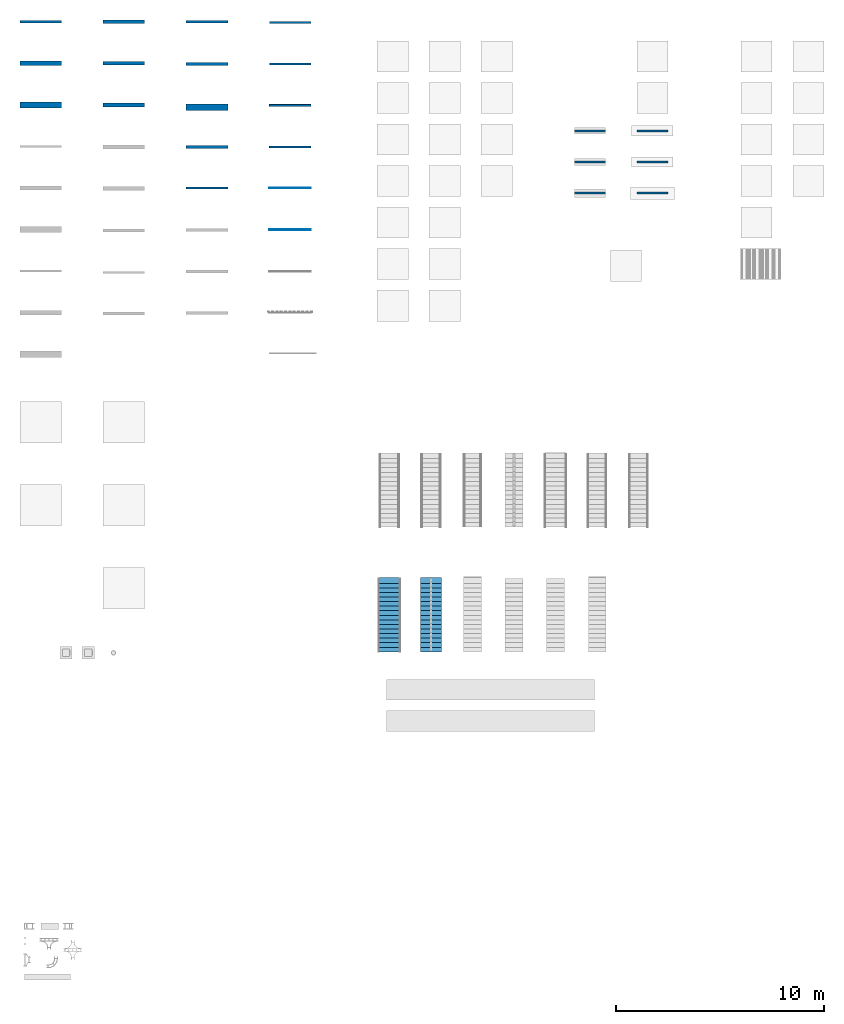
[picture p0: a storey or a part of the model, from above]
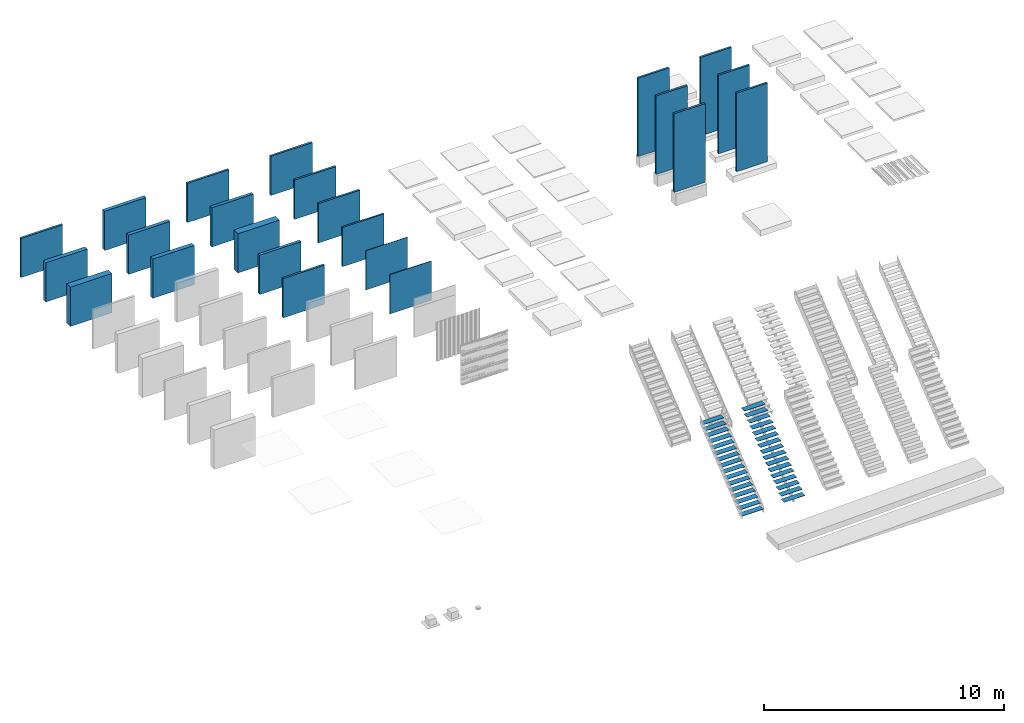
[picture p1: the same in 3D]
Properties of the parts of a building model (IFC2X3), part 1 of 3

# File
Description: ViewDefinition [CoordinationView_V2.0]
File name: 2012C-006
Time: 2013-12-05T17:48:52
Written by: The EXPRESS Data Manager Version 5.01.0100.02.64mod : 6 Jun 2012
Made in: 20130308_1515(x64) - Exporter 3.5.0.0 - Alternate UI 2.5.0.0
Comment: STEP Physical File produced by: The EXPRESS Data Manager Version 5.01.0100.02.64mod : 6 Jun 2012 * Module: EDMstepFileFactory/EDMstandAlone * Creation date: Thu Dec 05 17:48:52 2013 * Host: MDR_LPTP_BTO * Database: C:\Users\Martijn\AppData\Local\Temp\{F84D967D-EF22-411A-948F-E8C0A9D42476}\ifc * Database version: 5507 * Database creation date: Thu Dec 05 17:48:46 2013 * Schema: IFC2X3 * Model: DataRepository.ifc * Model creation date: Thu Dec 05 17:48:46 2013 * Header model: DataRepository.ifc_HeaderModel * Header model creation date: Thu Dec 05 17:48:46 2013 * EDMuser: sdai-user * EDMgroup: sdai-group * License ID and type: 5605 : Permanent license. Expiry date: * EDMstepFileFactory options: 020000

# IfcProject, 2012C-006
LongName: Dutch Revit Standards; Phase: VOORLOPIG

# IfcSite, Surface:79234
RefLatitude: 42, 24, 53, 508911; RefLongitude: -71, -15, -29, -58837; RefElevation: 0 mm
Dimensions - Projected Area: 13.67 m2; Surface Area: 13.67 m2
Identity Data - Name: 90_site
Materials and Finishes - Material: 97_terreinbeplanting_gras
Phasing - Phase Created: Renvooi

# IfcBuilding
Pset_BuildingCommon - NumberOfStoreys: 1
Identity Data - leverancier_bedrijfsnaam: Revit GebruikersGroep; leverancier_email: info@revitgg.nl; leverancier_fax: +31 (0)318 64 85 03; leverancier_plaats: Ede; leverancier_postadres: Postbus 7001; leverancier_postcode: 6710 CB; leverancier_telefoonnummer: +31 (0)318 69 84 57; opdrachtgever_bedrijfsnaam: Revit GebruikersGroep; project_huisadres: Horaplantsoen 20; project_plaats: Ede; project_postcode: 6717 LT; rgd_objectnummer: objectnummer
Other - Project Name: Dutch Revit Standards; Project Number: 2012C-006; Project Status: VOORLOPIG
Text - opdrachtgever_projectmanager: opdrachtgever_projectmanager

# IfcBuildingStorey, 00_begane grond
LongName: 00_begane grond; Elevation: 0 mm
Graphics - Color: 0; Line Pattern: -3000010; Line Weight: 1; Symbol: 00_LAB_niveau: structural_links; Symbol at End 1 Default: yes; Symbol at End 2 Default: no
Constraints - Elevation Base: Project Base Point; Elevation: -1000 mm
Identity Data - Building Story: no; Name: -1_fundering; Structural: yes
Extents - Scope Box: totaal
Dimensions - Computation Height: 0 mm

# IfcCovering: Basic Ceiling:45_CEI_plafond_MEP_host, Basic Ceiling:45_CEI_plafond_MEP_host:55413
In: 00_begane grond
PredefinedType: CEILING
Pset_CoveringCommon - Reference: 45_CEI_plafond_MEP_host
Constraints - Height Offset From Level: 2600 mm; Level: Level: 00_begane grond; Room Bounding: yes
Dimensions - Area: 4 m2; Perimeter: 8000 mm
Fire Protection - brandwerend: no; ontvlambaar: no
Phasing - Phase Created: Renvooi
Analytical Properties - Absorptance: 0.1; Roughness: 1
Identity Data - Description: te gebruiken om MEP elementen op te hosten; Type Mark: 45-99

# IfcCovering: Compound Ceiling:45_CEI_plafond_gipsplaat_610mm_wit, Compound Ceiling:45_CEI_plafond_gipsplaat_610mm_wit:58956
In: 00_begane grond
PredefinedType: CEILING; Material: <Unnamed> 24 mm, 45_gips_plafond_beplating_610mm 12.5 mm
Constraints - Height Offset From Level: 2600 mm; Level: Level: 00_begane grond; Room Bounding: yes
Dimensions - Area: 4 m2; Perimeter: 8000 mm; Volume: 0.146 m3
Fire Protection - brandwerend: no; ontvlambaar: no
Phasing - Phase Created: Renvooi
Analytical Properties - Absorptance: 0.1; Heat Transfer Coefficient (U): 52; Roughness: 1; Thermal mass: 11550; Thermal Resistance (R): 0.0192308
Construction - Thickness: 36.5 mm
Graphics - Coarse Scale Fill Color: 0
Identity Data - Assembly Code: 2H(45.11); Description: gipsplaat plafond op regelwerk; Keynote: d-40-046; Type Comments: platen 610mm breed; Type Mark: 45-01

# IfcCovering: Compound Ceiling:45_CEI_systeemplafond_1200x600_wit, Compound Ceiling:45_CEI_systeemplafond_1200x600_wit:59181
In: 00_begane grond
PredefinedType: CEILING; Material: 45_plafond_systeemplafond_1200x600_wit 15 mm
Pset_CoveringCommon - Reference: 45_CEI_systeemplafond_1200x600_wit; Finish: 45_plafond_systeemplafond_1200x600_wit;; TotalThickness: 4572 mm
Constraints - Height Offset From Level: 2600 mm; Level: Level: 00_begane grond; Room Bounding: yes
Dimensions - Area: 4 m2; Perimeter: 8000 mm; Volume: 0.06 m3
Fire Protection - brandwerend: no; ontvlambaar: no
Phasing - Phase Created: Renvooi
Analytical Properties - Absorptance: 0.1; Heat Transfer Coefficient (U): 3.8; Roughness: 1; Thermal mass: 5829; Thermal Resistance (R): 0.263158
Construction - Thickness: 15 mm
Graphics - Coarse Scale Fill Color: 0
Identity Data - Assembly Code: 2H(45.12); Description: systeemplafond, tegels 1200x600mm; Keynote: d-40-000; Type Comments: wit gekleurd; Type Mark: 45-04

# IfcCovering: Compound Ceiling:45_CEI_systeemplafond_600x600_rood, Compound Ceiling:45_CEI_systeemplafond_600x600_rood:59157
In: 00_begane grond
PredefinedType: CEILING; Material: 45_plafond_systeemplafond_600x600_donkerrood 15 mm
Pset_CoveringCommon - Reference: 45_CEI_systeemplafond_600x600_rood; Finish: 45_plafond_systeemplafond_600x600_donkerrood;; TotalThickness: 4572 mm
Constraints - Height Offset From Level: 2600 mm; Level: Level: 00_begane grond; Room Bounding: yes
Dimensions - Area: 4 m2; Perimeter: 8000 mm; Volume: 0.06 m3
Fire Protection - brandwerend: no; ontvlambaar: no
Phasing - Phase Created: Renvooi
Analytical Properties - Absorptance: 0.1; Heat Transfer Coefficient (U): 3.8; Roughness: 1; Thermal mass: 5829; Thermal Resistance (R): 0.263158
Construction - Thickness: 15 mm
Graphics - Coarse Scale Fill Color: 0
Identity Data - Assembly Code: 2H(45.12); Description: systeemplafond, tegels 600x600mm; Keynote: d-40-000; Type Comments: rood gekleurd; Type Mark: 45-02

# IfcCovering: Compound Ceiling:45_CEI_systeemplafond_600x600_wit, Compound Ceiling:45_CEI_systeemplafond_600x600_wit:59123
In: 00_begane grond
PredefinedType: CEILING; Material: 45_plafond_systeemplafond_600x600_wit 15 mm
Pset_CoveringCommon - Reference: 45_CEI_systeemplafond_600x600_wit; Finish: 45_plafond_systeemplafond_600x600_wit;; TotalThickness: 4572 mm
Constraints - Height Offset From Level: 2600 mm; Level: Level: 00_begane grond; Room Bounding: yes
Dimensions - Area: 4 m2; Perimeter: 8000 mm; Volume: 0.06 m3
Fire Protection - brandwerend: no; ontvlambaar: no
Phasing - Phase Created: Renvooi
Analytical Properties - Absorptance: 0.1; Heat Transfer Coefficient (U): 3.8; Roughness: 1; Thermal mass: 5829; Thermal Resistance (R): 0.263158
Construction - Thickness: 15 mm
Graphics - Coarse Scale Fill Color: 0
Identity Data - Assembly Code: 2H(45.12); Description: systeemplafond, tegels 600x600mm; Keynote: d-40-000; Type Comments: wit gekleurd; Type Mark: 45.03

# IfcCurtainWall: Curtain Wall:21_CW_binnendoos_SAB90_500, Curtain Wall:21_CW_binnendoos_SAB90_500:160824
In: 00_begane grond
Type - Construction - Automatically Embed: no; Curtain Panel: 27_CWP_SAB90_500: SAB90_500; Function: Exterior; Join Condition: Not Defined
Type - Fire Protection - ontvlambaar: no
Type - Horizontal Grid - Adjust for Mullion Size: yes; Layout: Fixed Distance; Spacing: 500 mm
Type - Identity Data - Assembly Code: 2D(21.13); Description: binnendoos SAB90; Type Comments: paneelbreedte 500mm; Type Mark: 41-01
Type - Vertical Grid - Adjust for Mullion Size: no; Spacing: 100 mm
Pset_CurtainWallCommon - Reference: 21_CW_binnendoos_SAB90_500; IsExternal: yes
Constraints - Base Constraint: Level: 00_begane grond; Base is Attached: no; Base Offset: 0 mm; Related to Mass: no; Room Bounding: yes; Top is Attached: no; Top Offset: 0 mm; Unconnected Height: 2000 mm
Dimensions - Area: 4.56 m2; Length: 2280 mm
Fire Protection - brandwerend: no
Horizontal Grid - Angle: 0 deg; Justification: Beginning; Number: 3; Offset: 0 mm
Phasing - Phase Created: Renvooi
Structural - Enable Analytical Model: no; Structural: no; Structural Usage: Non-bearing
Vertical Grid - Angle: 0 deg; Justification: Beginning; Number: 2; Offset: 0 mm

# IfcCurtainWall: Curtain Wall:21_CW_gevelbeplating_SAB35_1035, Curtain Wall:21_CW_gevelbeplating_SAB35_1035:60482
In: 00_begane grond
Type - Construction - Automatically Embed: no; Curtain Panel: 21_CWP_SAB35_1035: SAB35_1035; Function: Exterior; Join Condition: Not Defined
Type - Fire Protection - ontvlambaar: no
Type - Horizontal Grid - Adjust for Mullion Size: no
Type - Identity Data - Assembly Code: 2D(41.12); Description: buitenwandafwerking, bekleding, SAB35; Type Comments: paneelbreedte 1035mm; Type Mark: 41-02
Type - Vertical Grid - Adjust for Mullion Size: no; Layout: Fixed Distance; Spacing: 1035 mm
Pset_CurtainWallCommon - Reference: 21_CW_gevelbeplating_SAB35_1035; IsExternal: yes
Constraints - Base Constraint: Level: 00_begane grond; Base is Attached: no; Base Offset: 0 mm; Related to Mass: no; Room Bounding: yes; Top is Attached: no; Top Offset: 0 mm; Unconnected Height: 2000 mm
Dimensions - Area: 4.14 m2; Length: 2070 mm
Fire Protection - brandwerend: no
Horizontal Grid - Angle: 0 deg; Justification: Beginning; Number: 4; Offset: 0 mm
Phasing - Phase Created: Renvooi
Structural - Enable Analytical Model: no; Structural: no; Structural Usage: Non-bearing
Vertical Grid - Angle: 0 deg; Justification: Beginning; Number: 1; Offset: 0 mm

# IfcFlowFitting: T-stuk, radius_300, 61_CTF_kabelgoot_open_Tsplitsing:T-stuk, radius_300:191225
In: 00_begane grond
Type - Classification: 3B(61.30) (Uniformat)
Type - Dimensions - Radius: 300 mm
Type - Identity Data - Assembly Code: 3B(61.30); Description: kabelgoot, open; Type Comments: T-stuk, radius 300mm; Type Mark: 61-04-01
Constraints - Host: Level : 00_begane grond; Level: Level: 00_begane grond; Offset: 0 mm
Dimensions - Rung Height: 25 mm; Rung Space: 225 mm; Rung Width: 25 mm; Size: 150 mmx100 mmø-150 mmx100 mmø-150 mmx100 mmø; Thickness: 25 mm; Tray Height: 100 mm; Tray Length: 80 mm; Tray Width 1: 150 mm; Tray Width 3: 150 mm
Graphics - Use Annotation Scale: yes
Identity Data - Mark: 5
Other - lengte_1: 273.861 mm; lengte_2: 101.139 mm; lengte_3: 750 mm; radius_label: 300 mm; radius_label_1: 325 mm; zichtbaarheid_1: yes; zichtbaarheid_2: no; zichtbaarheid_3: yes; zichtbaarheid_4: yes
Phasing - Phase Created: Renvooi

# IfcFlowFitting: bocht verticaal binnen, standaard, 61_CTF_kabelgoot_open_bocht_verticaal_binnen:bocht verticaal binnen, standaard:195199
In: 00_begane grond
Type - Classification: 3B(61.30) (Uniformat)
Type - Identity Data - Assembly Code: 3B(61.30); Description: kabelgoot, open; Type Comments: bocht verticaal, binnen; Type Mark: 61-02-01
Constraints - Host: Level : 00_begane grond; Level: Level: 00_begane grond; Offset: 492.42 mm
Dimensions - Angle: 90 deg; Bend Radius: 300 mm; Rung Height: 25.4 mm; Rung Space: 250 mm; Rung Width: 25.4 mm; Size: 300 mmx100 mmø-300 mmx100 mmø; Thickness: 25.4 mm; Tray Height: 100 mm; Tray Length: 80 mm; Tray Width: 300 mm
Graphics - Use Annotation Scale: yes
Identity Data - Mark: 6
Other - Bend or Fitting: Fitting; Bend Radius Label: 350 mm; booglengte: 549.78 mm; hoek_1: 45 deg; hoek_2: 180 deg; hoek_3: 22.5 deg; hoek_4: 67.5 deg; lengte_1: 350 mm; lengte_2: 387.3 mm; sport_lengte: 249.2 mm; sport_lengte_half: 12.7 mm; zichtbaar_1: yes; zichtbaar_2: no
Phasing - Phase Created: Renvooi

# IfcFlowFitting: bocht verticaal buiten, standaard, 61_CTF_kabelgoot_open_bocht_verticaal_buiten:bocht verticaal buiten, standaard:188274
In: 00_begane grond
Type - Classification: 3B(61.30) (Uniformat)
Type - Identity Data - Assembly Code: 3B(61.30); Description: kabelgoot, open; Type Comments: bocht verticaal, buiten; Type Mark: 61-03-01
Constraints - Host: Level : 00_begane grond; Level: Level: 00_begane grond; Offset: 492.42 mm
Dimensions - Bend Radius: 300 mm; hoek: 90 deg; Rung Height: 25.4 mm; Rung Space: 228.6 mm; Rung Width: 25.4 mm; Size: 300 mmx100 mmø-300 mmx100 mmø; Thickness: 25.4 mm; Tray Height: 100 mm; Tray Length: 80 mm; Tray Width: 300 mm
Graphics - Use Annotation Scale: yes
Identity Data - Mark: 4
Other - Bend or Fitting: Fitting; boog_lengte: 549.78 mm; buigstraal_buitenrand: 350 mm; hoek_2: 180 deg; hoek_3: 22.5 deg; hoek_4: 67.5 deg; hoek 1: 45 deg; lengte_1: 312.7 mm; lengte_2: 350 mm; sport_breedte_half: 12.7 mm; sport_lengte: 249.2 mm; zichtbaar 1: yes; zichtbaar 2: no
Phasing - Phase Created: Renvooi

# IfcFlowFitting: bocht, standaard, 61_CTF_kabelgoot_open_bocht_horizontaal:bocht, standaard:207840
In: 00_begane grond
Type - Classification: 3B(61.30) (Uniformat)
Type - Identity Data - Assembly Code: 3B(61.30); Description: kabelgoot, open; Type Comments: bocht horizontaal; Type Mark: 61-07-01
Constraints - Host: Level : 00_begane grond; Level: Level: 00_begane grond; Offset: 0 mm
Dimensions - Angle: 90 deg; Bend Radius: 300 mm; Rung Height: 25 mm; Rung Space: 225 mm; Rung Width: 25 mm; Size: 150 mmx100 mmø-150 mmx100 mmø; Thickness: 25 mm; Tray Height: 100 mm; Tray Length: 80 mm; Tray Width: 150 mm
Graphics - Use Annotation Scale: yes
Identity Data - Mark: 9
Other - Bend or Fitting: Fitting; booglengte: 589.05 mm; buigstraal_midden: 375 mm; hoek_1: 45 deg; hoek_2: 180 deg; hoek_3: 22.5 deg; hoek_4: 67.5 deg; lengte_1: 375 mm; lengte_2: 325 mm; lengte_3: 100 mm; offset: 50 mm; zichtbaar_1: yes; zichtbaar_2: no
Phasing - Phase Created: Renvooi

# IfcFlowFitting: kruising, radius_300, 61_CTF_kabelgoot_open_kruising:kruising, radius_300:217844
In: 00_begane grond
Type - Classification: 3B(61.30) (Uniformat)
Type - Dimensions - Radius: 300 mm
Type - Identity Data - Assembly Code: 3B(61.30); Description: kabelgoot, open; Type Comments: kruising, radius 300mm; Type Mark: 61-08-01
Constraints - Host: Level : 00_begane grond; Level: Level: 00_begane grond; Offset: 0 mm
Dimensions - Rung Height: 25 mm; Rung Space: 225 mm; Rung Width: 25 mm; Size: 150 mmx100 mmø-150 mmx100 mmø-150 mmx100 mmø-150 mmx100 mmø; Thickness: 25 mm; Tray Height: 100 mm; Tray Length: 80 mm; Tray Width 1: 150 mm; Tray Width 3: 150 mm
Graphics - Use Annotation Scale: yes
Identity Data - Mark: 10
Other - lengte_1: 273.861 mm; lengte_2: 101.139 mm; lengte_3: 750 mm; radius_boog: 300 mm; radius_boog_1: 325 mm; zichtbaar_1: yes; zichtbaar_2: no; zichtbaar_3: yes; zichtbaar_4: yes
Phasing - Phase Created: Renvooi

# IfcFlowFitting: verbindingsstuk, standaard, 61_CTF_kabelgoot_open_verbinding:verbindingsstuk, standaard:196779
In: 00_begane grond
Type - Classification: 3B(61.30) (Uniformat)
Type - Identity Data - Assembly Code: 3B(61.30); Description: kabelgoot, open; Type Comments: koppelstuk, 100mm; Type Mark: 61-05-01
Constraints - Host: Level : 00_begane grond; Level: Level: 00_begane grond; Offset: 0 mm
Dimensions - Bend Radius: 300 mm; Rung Height: 25 mm; Rung Space: 225 mm; Rung Width: 25 mm; Size: 300 mmx100 mmø-300 mmx100 mmø; Thickness: 25 mm; Tray Height: 100 mm; Tray Length: 75 mm; Tray Width: 300 mm
Graphics - Use Annotation Scale: yes
Identity Data - Mark: 7
Phasing - Phase Created: Renvooi

# IfcFlowFitting: verloopstuk, standaard, 61_CTF_kabelgoot_open_verloop:verloopstuk, standaard:206094
In: 00_begane grond
Type - Classification: 3B(61.30) (Uniformat)
Type - Identity Data - Assembly Code: 3B(61.30); Description: kabelgoot, open; Type Comments: verloopstuk; Type Mark: 61-06-01
Constraints - Host: Level : 00_begane grond; Level: Level: 00_begane grond; Offset: 0 mm
Dimensions - OffsetHeight: 0.164042; OffsetWidth: 0.984252; Rung Height: 25 mm; Rung Space: 225 mm; Rung Width: 25 mm; Size: 600 mmx100 mmø-300 mmx100 mmø; Thickness: 25 mm; Tray Height 1: 100 mm; Tray Height 2: 100 mm; Tray Length: 300 mm; Tray Width 1: 600 mm; Tray Width 2: 300 mm
Graphics - Use Annotation Scale: yes
Identity Data - Mark: 8
Other - breedte_offset: 3048 mm; hoogte_offset: 3048 mm; lengte_1: 3048 mm; offset_1: 50 mm; offset_2: 50 mm; profiel_offset_horizontaal: 0 mm; profiel_offset_verticaal: 0 mm
Phasing - Phase Created: Renvooi

# IfcFlowSegment: Cable Tray with Fittings:61_CT_kabelgoot_open, Cable Tray with Fittings:61_CT_kabelgoot_open:180304
In: 00_begane grond
Type - Electrical - Bend Radius Multiplier: 1
Type - Fittings - Cross: 61_CTF_kabelgoot_open_kruising: kruising, radius_300; Horizontal Bend: 61_CTF_kabelgoot_open_bocht_horizontaal: bocht, standaard; Tee: 61_CTF_kabelgoot_open_Tsplitsing: T-stuk, radius_300; Transition: 61_CTF_kabelgoot_open_verloop: verloopstuk, standaard; Union: 61_CTF_kabelgoot_open_verbinding: verbindingsstuk, standaard; Vertical Inside Bend: 61_CTF_kabelgoot_open_bocht_verticaal_binnen: bocht verticaal binnen, standaard; Vertical Outside Bend: 61_CTF_kabelgoot_open_bocht_verticaal_buiten: bocht verticaal buiten, standaard
Type - Identity Data - Assembly Code: 3B(61.3); Description: kabelgoot, open; Type Comments: met koppelstukken; Type Mark: 61-01-01
Pset_DistributionFlowElementCommon - Reference: 61_CT_kabelgoot_open
Constraints - End Offset: 492.42 mm; Horizontal Justification: Center; Offset: 492.42 mm; Reference Level: Level: 00_begane grond; Start Offset: 492.42 mm; Vertical Justification: Middle
Dimensions - Height: 100 mm; Length: 860 mm; Rung Space: 250 mm; Size: 300 mmx100 mmø; Width: 300 mm
Electrical - Bottom Elevation: 442.42 mm; Top Elevation: 542.42 mm
Identity Data - Mark: 2
Phasing - Phase Created: Renvooi

# IfcFlowSegment: Cable Tray without Fittings:61_CT_kabelgoot_open, Cable Tray without Fittings:61_CT_kabelgoot_open:206202
In: 00_begane grond
Type - Electrical - Bend Radius Multiplier: 1
Type - Identity Data - Assembly Code: 3B(61.3); Description: kabelgoot, open; Type Comments: zonder koppelstukken; Type Mark: 61-01-02
Pset_DistributionFlowElementCommon - Reference: 61_CT_kabelgoot_open
Constraints - End Offset: 0 mm; Horizontal Justification: Center; Offset: 0 mm; Reference Level: Level: 00_begane grond; Start Offset: 0 mm; Vertical Justification: Middle
Dimensions - Height: 100 mm; Length: 2220 mm; Rung Space: 228.6 mm; Size: 300 mmx100 mmø; Width: 300 mm
Electrical - Bottom Elevation: -50 mm; Top Elevation: 50 mm
Identity Data - Mark: 3
Phasing - Phase Created: Renvooi

# IfcFlowTerminal: aanvoer_plafondrooster_kanaaldiameter_250, 57_AT_plafondrooster_toev_rond_kanaal_FB:aanvoer_plafondrooster_kanaaldiameter_250:221553
In: 00_begane grond
Type - Classification: 3A(57.5) (Uniformat)
Type - Constraints - Default Elevation: 1219.2 mm
Type - Dimensions - breedte_plafondplaat: 600 mm; diameter_aansluiting: 250 mm; kanaal_radius: 125 mm; lengte_plafondplaat: 600 mm; plenum_breedte: 350 mm; plenum_hoogte: 330 mm; plenum_lengte: 350 mm
Type - Identity Data - Assembly Code: 3A(57.5); Description: aanvoerpunt plafondplaat; Manufacturer: RevitGG; Type Comments: kanaaldiameter = 250mm; Type Mark: AT-06-05; URL: www.revitgg.nl
Type - Mechanical - Flow - statisch_drukverlies: 0
Type - Pset_AirTerminalTypeCommon - Shape: ROUND
Pset_ManufacturerTypeInformation - Manufacturer: RevitGG
Constraints - Offset: 0 mm; Work Plane: Level : 00_begane grond
Dimensions - Size: 250 mmø
Identity Data - Mark: 6
Mechanical - System Classification: Supply Air
Mechanical - Flow - debiet_aanvoer: 0 m3/s
Other - Schedule Level: Level: 00_begane grond
Phasing - Phase Created: Renvooi

# IfcFlowTerminal: afvoer_plafondrooster_kanaaldiameter_250, 57_AT_plafondrooster_afv_rond_kanaal_FB:afvoer_plafondrooster_kanaaldiameter_250:124771
In: 00_begane grond
Type - Classification: 3A(57.5) (Uniformat)
Type - Dimensions - breedte_plafondplaat: 600 mm; diameter_aansluiting: 250 mm; kanaal_radius: 125 mm; lengte_plafondplaat: 600 mm; plenum_breedte: 350 mm; plenum_hoogte: 330 mm; plenum_lengte: 350 mm
Type - Identity Data - Assembly Code: 3A(57.5); Description: aanvoerpunt plafondplaat 600x600mm; Manufacturer: RevitGG; Type Comments: kanaaldiameter 250mm; Type Mark: AT-05-05; URL: www.revitgg.nl
Type - Mechanical - Flow - statisch_drukverlies: 0
Type - Pset_AirTerminalTypeCommon - Shape: ROUND
Pset_ManufacturerTypeInformation - Manufacturer: RevitGG
Constraints - Offset: 0 mm; Work Plane: Level : 00_begane grond
Dimensions - Size: 250 mmø
Identity Data - Mark: 5
Mechanical - System Classification: Return Air
Mechanical - Flow - debiet_afzuig: 0 m3/s
Other - Schedule Level: Level: 00_begane grond
Phasing - Phase Created: Renvooi

# IfcFlowTerminal: afvoer_rozet_kanaaldiameter_200, 57_AT_afv_rozet_FB:afvoer_rozet_kanaaldiameter_200:148100
In: 00_begane grond
Type - Classification: 3A(57.30) (Uniformat)
Type - Dimensions - diameter_aansluiting: 200 mm; kanaal_aansluit_hoogte: 50 mm; kanaal_radius: 100 mm; rooster_diameter: 250 mm; rooster_hoogte: 30 mm; rooster_radius: 125 mm
Type - Identity Data - Assembly Code: 3A(57.30); Description: afzuigrozet, generiek; Manufacturer: RevitGG; Type Comments: kanaaldiameter 200mm; Type Mark: AT-07-04; URL: www.revitgg.nl
Type - Mechanical - Flow - statisch_drukverlies: 0
Type - Pset_AirTerminalTypeCommon - Shape: ROUND
Pset_ManufacturerTypeInformation - Manufacturer: RevitGG
Constraints - Offset: 0 mm; Work Plane: Level : 00_begane grond
Dimensions - Size: 200 mmø
Identity Data - Mark: 7
Mechanical - System Classification: Return Air
Mechanical - Flow - debiet_afzuig: 0 m3/s
Other - Schedule Level: Level: 00_begane grond
Phasing - Phase Created: Renvooi

# IfcFooting: Foundation Slab:16_SFO_funderingsplaat_beton_generiek_300, Foundation Slab:16_SFO_funderingsplaat_beton_generiek_300:67787
In: 00_begane grond
Material: layer 300 mm
Constraints - Height Offset From Level: 0 mm; Level: Level: 00_begane grond; Related to Mass: no
Dimensions - Area: 2.25 m2; Elevation at Bottom: -300 mm; Length: 1500 mm; Perimeter: 6000 mm; Thickness: 300 mm; Volume: 0.675 m3; Width: 1500 mm
Phasing - Phase Created: Renvooi
Structural - Enable Analytical Model: yes; Rebar Cover - Bottom Face: Rebar Cover Settings: Rebar Cover 1; Rebar Cover - Other Faces: Rebar Cover Settings: Rebar Cover 1; Rebar Cover - Top Face: Rebar Cover Settings: Rebar Cover 1; Structural: yes
Analytical Properties - Absorptance: 0.1; Heat Transfer Coefficient (U): 3.48667; Roughness: 1; Thermal mass: 453330; Thermal Resistance (R): 0.286807
Construction - Default Thickness: 300 mm
Graphics - Coarse Scale Fill Color: 8421504; Coarse Scale Fill Pattern: Solid fill
Identity Data - Assembly Code: 2A(16.0); Description: Funderingsplaat beton,; Keynote: d-16-000; Type Comments: d = 300mm; Type Mark: 16-01

# IfcFooting: Foundation Slab:16_SFO_funderingsplaat_ihwg_beton_C30/37, Foundation Slab:16_SFO_funderingsplaat_ihwg_beton_C30/37:68150
In: 00_begane grond
Material: 16_beton_ihwg_C30/35 300 mm
Constraints - Height Offset From Level: 0 mm; Level: Level: 00_begane grond; Related to Mass: no
Dimensions - Area: 2.25 m2; Elevation at Bottom: -300 mm; Length: 1500 mm; Perimeter: 6000 mm; Thickness: 300 mm; Volume: 0.675 m3; Width: 1500 mm
Phasing - Phase Created: Renvooi
Structural - Enable Analytical Model: yes; Rebar Cover - Bottom Face: Rebar Cover Settings: Rebar Cover 1; Rebar Cover - Other Faces: Rebar Cover Settings: Rebar Cover 1; Rebar Cover - Top Face: Rebar Cover Settings: Rebar Cover 1; Structural: yes
Analytical Properties - Absorptance: 0.1; Heat Transfer Coefficient (U): 3.48667; Roughness: 1; Thermal mass: 453330; Thermal Resistance (R): 0.286807
Construction - Default Thickness: 300 mm
Graphics - Coarse Scale Fill Color: 8421504; Coarse Scale Fill Pattern: Solid fill
Identity Data - Assembly Code: 2A(16.0); Description: Funderingsplaat beton, in het werk gestort; Keynote: d-16-000; Type Comments: klasse C30/37. d = 300mm; Type Mark: 16-02
Materials and Finishes - Structural Material: 16_beton_ihwg_C30/35

# IfcFooting: Wall Foundation:16_SFO_ihwg beton_C30-35_500x200, Wall Foundation:16_SFO_ihwg beton_C30-35_500x200:317217
In: 00_begane grond
PredefinedType: STRIP_FOOTING; Material: 16_beton_ihwg_C30/35
Structural - Structural Usage: Bearing; Enable Analytical Model: no; Rebar Cover - Bottom Face: Rebar Cover Settings: Rebar Cover 1; Rebar Cover - Other Faces: Rebar Cover Settings: Rebar Cover 1; Rebar Cover - Top Face: Rebar Cover Settings: Rebar Cover 1
Materials and Finishes - Structural Material: 16_beton_ihwg_C30/35
Identity Data - Assembly Code: 2A(16.12); Description: strookfundering ihw gestort beton, C30/35; Keynote: d-16-010; Type Comments: bxh 500x200mm; Type Mark: 16-03
Dimensions - Default End Extension Length: 250 mm; Do Not Break At Inserts: no; Foundation Thickness: 200 mm; Width: 500 mm; Elevation at Bottom: -200 mm; Length: 2000 mm; Volume: 0.2 m3
Constraints - Eccentricity: 0 mm
Phasing - Phase Created: Renvooi

# IfcFooting: Wall Foundation:16_SFO_ihwg beton_C30-35_500x250, Wall Foundation:16_SFO_ihwg beton_C30-35_500x250:317290
In: 00_begane grond
PredefinedType: STRIP_FOOTING; Material: 16_beton_ihwg_C30/35
Structural - Structural Usage: Bearing; Enable Analytical Model: no; Rebar Cover - Bottom Face: Rebar Cover Settings: Rebar Cover 1; Rebar Cover - Other Faces: Rebar Cover Settings: Rebar Cover 1; Rebar Cover - Top Face: Rebar Cover Settings: Rebar Cover 1
Materials and Finishes - Structural Material: 16_beton_ihwg_C30/35
Identity Data - Assembly Code: 2A(16.12); Description: strookfundering ihw gestort beton, C30/35; Keynote: d-16-010; Type Comments: bxh 500x250mm; Type Mark: 16-04
Dimensions - Default End Extension Length: 250 mm; Do Not Break At Inserts: yes; Foundation Thickness: 250 mm; Width: 500 mm; Elevation at Bottom: -250 mm; Length: 2000 mm; Volume: 0.25 m3
Constraints - Eccentricity: 0 mm
Phasing - Phase Created: Renvooi

# IfcFooting: Wall Foundation:16_SFO_ihwg beton_C30-35_600x300, Wall Foundation:16_SFO_ihwg beton_C30-35_600x300:317374
In: 00_begane grond
PredefinedType: STRIP_FOOTING; Material: 16_beton_ihwg_C30/35
Structural - Structural Usage: Bearing; Enable Analytical Model: no; Rebar Cover - Bottom Face: Rebar Cover Settings: Rebar Cover 1; Rebar Cover - Other Faces: Rebar Cover Settings: Rebar Cover 1; Rebar Cover - Top Face: Rebar Cover Settings: Rebar Cover 1
Materials and Finishes - Structural Material: 16_beton_ihwg_C30/35
Identity Data - Assembly Code: 2A(16.12); Description: strookfundering ihw gestort beton, C30/35; Keynote: d-16-010; Type Comments: bxh 600x300mm; Type Mark: 16-05
Dimensions - Default End Extension Length: 300 mm; Do Not Break At Inserts: yes; Foundation Thickness: 300 mm; Width: 600 mm; Elevation at Bottom: -300 mm; Length: 2100 mm; Volume: 0.378 m3
Constraints - Eccentricity: 0 mm
Phasing - Phase Created: Renvooi

# IfcFooting: Wall Foundation:16_SFO_prefab beton_C35-45_300x500, Wall Foundation:16_SFO_prefab beton_C35-45_300x500:317420
In: 00_begane grond
PredefinedType: STRIP_FOOTING; Material: 16_beton_prefab_C35-45
Structural - Structural Usage: Bearing; Enable Analytical Model: no; Rebar Cover - Bottom Face: Rebar Cover Settings: Rebar Cover 1; Rebar Cover - Other Faces: Rebar Cover Settings: Rebar Cover 1; Rebar Cover - Top Face: Rebar Cover Settings: Rebar Cover 1
Materials and Finishes - Structural Material: 16_beton_prefab_C35-45
Identity Data - Assembly Code: 2A(16.12); Description: funderingsbalk prefab beton, C35/45; Keynote: d-16-000; Type Comments: bxh 300xx500mm; Type Mark: 16-06
Dimensions - Default End Extension Length: 0 mm; Do Not Break At Inserts: yes; Foundation Thickness: 500 mm; Width: 300 mm; Elevation at Bottom: -500 mm; Length: 1500 mm; Volume: 0.225 m3
Constraints - Eccentricity: 0 mm
Phasing - Phase Created: Renvooi

# IfcFooting: Wall Foundation:16_SFO_prefab beton_C35-45_350x550, Wall Foundation:16_SFO_prefab beton_C35-45_350x550:317423
In: 00_begane grond
PredefinedType: STRIP_FOOTING; Material: 16_beton_prefab_C35-45
Structural - Structural Usage: Bearing; Enable Analytical Model: no; Rebar Cover - Bottom Face: Rebar Cover Settings: Rebar Cover 1; Rebar Cover - Other Faces: Rebar Cover Settings: Rebar Cover 1; Rebar Cover - Top Face: Rebar Cover Settings: Rebar Cover 1
Materials and Finishes - Structural Material: 16_beton_prefab_C35-45
Identity Data - Assembly Code: 2A(16.12); Description: funderingsbalk prefab beton, C35/45; Keynote: d-16-000; Type Comments: bxh 350xx550mm; Type Mark: 16-07
Dimensions - Default End Extension Length: 0 mm; Do Not Break At Inserts: yes; Foundation Thickness: 550 mm; Width: 350 mm; Elevation at Bottom: -550 mm; Length: 1500 mm; Volume: 0.28875 m3
Constraints - Eccentricity: 0 mm
Phasing - Phase Created: Renvooi

# IfcFooting: Wall Foundation:16_SFO_prefab beton_C35-45_400x600, Wall Foundation:16_SFO_prefab beton_C35-45_400x600:317426
In: 00_begane grond
PredefinedType: STRIP_FOOTING; Material: 16_beton_prefab_C35-45
Structural - Structural Usage: Bearing; Enable Analytical Model: no; Rebar Cover - Bottom Face: Rebar Cover Settings: Rebar Cover 1; Rebar Cover - Other Faces: Rebar Cover Settings: Rebar Cover 1; Rebar Cover - Top Face: Rebar Cover Settings: Rebar Cover 1
Materials and Finishes - Structural Material: 16_beton_prefab_C35-45
Identity Data - Assembly Code: 2A(16.12); Description: funderingsbalk prefab beton, C35/45; Keynote: d-16-000; Type Comments: bxh 400xx600mm; Type Mark: 16-08
Dimensions - Default End Extension Length: 0 mm; Do Not Break At Inserts: yes; Foundation Thickness: 600 mm; Width: 400 mm; Elevation at Bottom: -600 mm; Length: 1500 mm; Volume: 0.36 m3
Constraints - Eccentricity: 0 mm
Phasing - Phase Created: Renvooi

# IfcMember: Carriage:24_STC_middenboom_hout_vuren_100x50 (2)
In: 00_begane grond
Type - PredefinedType: STRINGER
Pset_MemberCommon - LoadBearing: yes; IsExternal: no; Span: 100 mm; Slope: 0 deg
Constraints - Lower End Cut: Vertical Cut; Trim Support at Upper: Do not trim; Upper End Cut: Vertical Cut
Phasing - Phase Created: Renvooi
Dimensions - Structural Depth On Landing: 50 mm; Structural Depth On Run: 50 mm; Total Depth: 350 mm; Width: 100 mm
Fire Protection - ontvlambaar: no
Identity Data - Assembly Code: 2G(24.0); Description: middenboom, vuren, 15x100mm; Keynote: d-24-000; Type Mark: CA_05
Name (Assembled Stair:Stair:...) | Reference
69261 Stringer 1 | 24_ST_houten trap_open_middenboom_b=850_op=185_aan=220
69309 Stringer 1 | 24_ST_stalen trap_open_middenboom_b=1000_op=185_aan=220

# IfcMember: Carriage:24_STC_middenboom_hout_vuren_45x100 (2)
In: 00_begane grond
Type - PredefinedType: STRINGER
Pset_MemberCommon - Reference: 24_ST_houten trap_open_gezadeld_b=850_op=185_aan=220; LoadBearing: yes; IsExternal: no; Span: 45 mm; Slope: 0 deg
Constraints - Lower End Cut: Vertical Cut; Trim Support at Upper: Do not trim; Upper End Cut: Vertical Cut
Phasing - Phase Created: Renvooi
Dimensions - Structural Depth On Landing: 100 mm; Structural Depth On Run: 100 mm; Total Depth: 350 mm; Width: 45 mm
Fire Protection - ontvlambaar: no
Identity Data - Assembly Code: 2G(24.0); Description: middenboom, vuren, 45x100mm; Keynote: d-24-000; Type Mark: CA_03
Name (Assembled Stair:Stair:...)
69257 Stringer 1
69257 Stringer 2

# IfcMember: Stringer:24_STS_trapboom_hout_vuren_15x50 (8)
In: 00_begane grond
Type - PredefinedType: STRINGER
Pset_MemberCommon - LoadBearing: yes; IsExternal: no; Span: 15 mm; Slope: 0 deg
Constraints - Lower End Cut: Vertical Cut; Trim Support at Upper: Do not trim; Upper End Cut: Vertical Cut
Phasing - Phase Created: Renvooi
Dimensions - Flip Section Profile: no; Structural Depth On Landing: 50 mm; Structural Depth On Run: 50 mm; Total Depth: 350 mm; Width: 15 mm
Fire Protection - ontvlambaar: no
Identity Data - Assembly Code: 2G(24.10); Description: trapboom, vuren, 15x50mm; Keynote: d-24-000
Name (Assembled Stair:Stair:...) | Reference
69280 Stringer 1 | 24_ST_stalen trap_gesloten_b=1000_op=185_aan=220
69280 Stringer 2 | 24_ST_stalen trap_gesloten_b=1000_op=185_aan=220
69283 Stringer 1 | 24_ST_stalen trap_open_b=850_op=185_aan=150
69283 Stringer 2 | 24_ST_stalen trap_open_b=850_op=185_aan=150
69288 Stringer 1 | 24_ST_stalen trap_open_b=850_op=185_aan=220
69288 Stringer 2 | 24_ST_stalen trap_open_b=850_op=185_aan=220
69305 Stringer 1 | 24_ST_stalen trap_open_b=1000_op=185_aan=350
69305 Stringer 2 | 24_ST_stalen trap_open_b=1000_op=185_aan=350

# IfcMember: Stringer:24_STS_trapboom_hout_vuren_45x50 (4)
In: 00_begane grond
Type - PredefinedType: STRINGER
Pset_MemberCommon - LoadBearing: yes; IsExternal: no; Span: 45 mm; Slope: 0 deg
Constraints - Lower End Cut: Vertical Cut; Trim Support at Upper: Do not trim; Upper End Cut: Vertical Cut
Phasing - Phase Created: Renvooi
Dimensions - Flip Section Profile: no; Structural Depth On Landing: 50 mm; Structural Depth On Run: 50 mm; Total Depth: 350 mm; Width: 45 mm
Fire Protection - ontvlambaar: no
Identity Data - Assembly Code: 2G(24.10); Description: trapboom, vuren, 45x50mm; Keynote: d-24-000
Name (Assembled Stair:Stair:...) | Reference
68679 Stringer 1 | 24_ST_houten trap_gesloten_b=850_op=185_aan=220
68679 Stringer 2 | 24_ST_houten trap_gesloten_b=850_op=185_aan=220
68953 Stringer 1 | 24_ST_houten trap_open_b=850_op=185_aan=220
68953 Stringer 2 | 24_ST_houten trap_open_b=850_op=185_aan=220

# IfcPlate: SAB35_1035 (2)
In: 00_begane grond
Type - ElementType: SAB35_1035
Type - Analytical Properties - Analytic Construction: <None>
Type - Dimensions - profiel_breedte: 1035 mm; profiel_diepte: 37 mm
Type - Identity Data - Assembly Code: 2D(41.12); Description: gevelbeplating, damwandprofiel, SAB35; OmniClass Number: 23.25.20.14.11.11.17; OmniClass Title: Infill Panels; Type Comments: paneelbreedte 1035mm; Type Mark: 41-02-01
Analysis Results - oppervlakte: 13.44 m2
Constraints - CALC_profiel_offset: 500 mm
Dimensions - Area: 2.07 m2; breedte: 3200 mm; dagmaat: 1035 mm; dagmaat_hoogte: 2000 mm; dikte: 0 mm; Height: 2000 mm; hoogte: 4200 mm; profiel_offset: 0 mm; Width: 1035 mm
Phasing - Phase Created: Renvooi
Pset_PlateCommon - IsExternal: yes; LoadBearing: yes; ThermalTransmittance: 0 kg/K/s3
Name (21_CWP_SAB35_1035:SAB35_1035:...)
60502
157321

# IfcPlate: SAB58KD_945 (2)
In: 00_begane grond
Type - ElementType: SAB58KD_945
Type - Analytical Properties - Analytic Construction: <None>
Type - Dimensions - profiel_breedte: 945 mm; profiel_diepte: 58 mm
Type - Identity Data - Assembly Code: 2C(47.10); Description: kouddak beplating, damwandprofiel, SAB58KD; OmniClass Number: 23.25.20.14.11.11.17; OmniClass Title: Infill Panels; Type Comments: paneelbreedte 945mm; Type Mark: 47-05-01
Analysis Results - oppervlakte: 13.44 m2
Constraints - CALC_profiel_offset: 560 mm
Dimensions - breedte: 3200 mm; dagmaat_hoogte: 1500 mm; dikte: 0 mm; Height: 1500 mm; hoogte: 4200 mm; profiel_offset: 60 mm
Phasing - Phase Created: Renvooi
Pset_PlateCommon - IsExternal: yes; LoadBearing: yes; ThermalTransmittance: 0 kg/K/s3
Name (27_CWP_SAB58KD_945:SAB58KD_945:...) | Area (m2) | dagmaat (mm) = Width (mm)
165322 | 1.4175 | 945
165325 | 0.8325 | 555

# IfcPlate: SAB90_500 (4)
In: 00_begane grond
Type - ElementType: SAB90_500
Type - Analytical Properties - Analytic Construction: <None>
Type - Dimensions - profiel_breedte: 500 mm; profiel_diepte: 92 mm
Type - Fire Protection - ontvlambaar: no
Type - Identity Data - Assembly Code: 2D(21.13); Description: stalen binnendoos, SAB90; OmniClass Number: 23.25.20.14.11.11.17; OmniClass Title: Infill Panels; Type Comments: plaatbreedte 500mm; Type Mark: 41-01-01; zelfsluitend: no
Analysis Results - oppervlakte: 13.44 m2
Constraints - CALC_profiel_offset: 500 mm
Dimensions - Area: 1.14 m2; dagmaat: 2280 mm; dagmaat_hoogte: 500 mm; dikte: 0 mm; Height: 500 mm; profiel_offset: 0 mm; Width: 2280 mm
Phasing - Phase Created: Renvooi
Pset_PlateCommon - IsExternal: yes; LoadBearing: yes; ThermalTransmittance: 0 kg/K/s3
Name (27_CWP_SAB90_500:SAB90_500:...)
160826
168635
168639
168643

# IfcRamp: Ramp:24_RA_hellingbaan_beton_prefab_300:1413, Ramp:24_RA_hellingbaan_beton_prefab_300:77835
In: 00_begane grond
Pset_RampCommon - Reference: 24_RA_hellingbaan_beton_prefab_300; IsExternal: no; HandicapAccessible: no; FireExit: no; HasNonSkidSurface: no; RequiredSlope: 30
Constraints - Base Level: Level: 00_begane grond; Base Offset: 0 mm; Top Level: Level: 01_eerste verdieping; Top Offset: 0 mm
Dimensions - Width: 1000 mm; Maximum Incline Length: 10000 mm
Fire Protection - brandwerend: no; ontvlambaar: no
Graphics - Down label: yes; Down text: DN; Show Up arrow in all views: no; Up label: yes; Up text: UP; Text Font: Arial; Text Size: 0.0082021
Identity Data - antislip: no; toegankelijk: no; vluchtweg: no; Assembly Code: 2G(24.20); Description: hellingbaan, b=1000mm; Keynote: d-24-000; Type Comments: prefab beton, 300mm; Type Mark: 24-14
Phasing - Phase Created: Renvooi
Construction - Function: Interior; Thickness: 300 mm
Materials and Finishes - Ramp Material: 24_beton_prefab_generiek
Other - Ramp Max Slope (1/x): 30; Shape: Thick

# IfcRamp: Ramp:24_RA_hellingbaan_beton_prefab_solid:79073, Ramp:24_RA_hellingbaan_beton_prefab_solid:79050
In: 00_begane grond
Pset_RampCommon - Reference: 24_RA_hellingbaan_beton_prefab_solid; IsExternal: no; HandicapAccessible: no; FireExit: no; HasNonSkidSurface: no; RequiredSlope: 30
Constraints - Base Level: Level: 00_begane grond; Base Offset: 0 mm; Top Level: Level: 01_eerste verdieping; Top Offset: 0 mm
Dimensions - Width: 1000 mm; Maximum Incline Length: 10000 mm
Fire Protection - brandwerend: no; ontvlambaar: no
Graphics - Down label: yes; Down text: DN; Show Up arrow in all views: no; Up label: yes; Up text: UP; Text Font: Arial; Text Size: 0.0082021
Identity Data - antislip: no; toegankelijk: no; vluchtweg: no; Assembly Code: 2G(24.20); Description: hellingbaan, b=1000mm; Keynote: d-24-000; Type Comments: prefab beton, 300mm; Type Mark: 24-15
Phasing - Phase Created: Renvooi
Other - Ramp Max Slope (1/x): 30; Shape: Solid
Materials and Finishes - Ramp Material: 24_beton_prefab_generiek
Construction - Function: Exterior; Thickness: 300 mm

# IfcRampFlight: Ramp:24_RA_hellingbaan_beton_prefab_300:1413, Ramp:24_RA_hellingbaan_beton_prefab_300:77835:1
In: 00_begane grond
Material: 24_beton_prefab_generiek
Pset_RampFlightCommon - Reference: 24_RA_hellingbaan_beton_prefab_300

# IfcRampFlight: Ramp:24_RA_hellingbaan_beton_prefab_solid:79073, Ramp:24_RA_hellingbaan_beton_prefab_solid:79050:1
In: 00_begane grond
Material: 24_beton_prefab_generiek
Pset_RampFlightCommon - Reference: 24_RA_hellingbaan_beton_prefab_solid

# IfcRoof: Basic Roof:27_RO_dakplaat_enkelschalig_PIR_135_33-90-12, Basic Roof:27_RO_dakplaat_enkelschalig_PIR_135_33-90-12:69928
In: 00_begane grond
Pset_RoofCommon - Reference: 27_RO_dakplaat_enkelschalig_PIR_135_33-90-12; IsExternal: yes; TotalArea: 2.25 m2; ProjectedArea: 2.25 m2
Constraints - Base Level: Level: 00_begane grond; Base Offset From Level: 0 mm; Cutoff Offset: 0 mm; Related to Mass: no; Room Bounding: yes
Construction - Fascia Depth: 0 mm; Maximum Ridge Height: 135 mm; Rafter Cut: Plumb Cut; Default Thickness: 135 mm
Dimensions - Area: 2.25 m2; Thickness: 135 mm; Volume: 0.30375 m3
Phasing - Phase Created: Renvooi
Analytical Properties - Absorptance: 0.1; Heat Transfer Coefficient (U): 0.321998; Roughness: 1; Thermal mass: 18473.2; Thermal Resistance (R): 3.10561
Graphics - Coarse Scale Fill Color: 8421504; Coarse Scale Fill Pattern: Solid fill
Identity Data - Assembly Code: 2B(27.22); Description: enkelschalige zelfdragende dakplaat, ribhoogte 123mm; Type Comments: 90mm PIR isolatie, onderplaat 12mm; Type Mark: 27-04

# IfcRoof: Basic Roof:27_RO_dakplaat_sandwich_PIR_106_20-3-80-3, Basic Roof:27_RO_dakplaat_sandwich_PIR_106_20-3-80-3:77055
In: 00_begane grond
Pset_RoofCommon - Reference: 27_RO_dakplaat_sandwich_PIR_106_20-3-80-3; IsExternal: yes; TotalArea: 2.25 m2; ProjectedArea: 2.25 m2
Constraints - Base Level: Level: 00_begane grond; Base Offset From Level: 0 mm; Cutoff Offset: 0 mm; Related to Mass: no; Room Bounding: yes
Construction - Fascia Depth: 0 mm; Maximum Ridge Height: 106 mm; Rafter Cut: Plumb Cut; Default Thickness: 106 mm
Dimensions - Area: 2.25 m2; Thickness: 106 mm; Volume: 0.2385 m3
Phasing - Phase Created: Renvooi
Analytical Properties - Absorptance: 0.1; Heat Transfer Coefficient (U): 0.367638; Roughness: 1; Thermal mass: 11556.1; Thermal Resistance (R): 2.72007
Graphics - Coarse Scale Fill Color: 8421504; Coarse Scale Fill Pattern: Solid fill
Identity Data - Assembly Code: 2B(27.22); Description: sandwich dakplaat, ribhoogte 80mm, tengel 20mm; Type Comments: 80mm PIR isolatie, onder- en bovenplaat 3mm; Type Mark: 27-05

# IfcRoof: Basic Roof:27_RO_generiek_200, Basic Roof:27_RO_generiek_200:69710
In: 00_begane grond
Pset_RoofCommon - Reference: 27_RO_generiek_200; IsExternal: yes; TotalArea: 2.25 m2; ProjectedArea: 2.25 m2
Constraints - Base Level: Level: 00_begane grond; Base Offset From Level: 0 mm; Cutoff Offset: 0 mm; Related to Mass: no; Room Bounding: yes
Construction - Fascia Depth: 0 mm; Maximum Ridge Height: 200 mm; Rafter Cut: Plumb Cut; Default Thickness: 200 mm
Dimensions - Area: 2.25 m2; Thickness: 200 mm; Volume: 0.45 m3
Phasing - Phase Created: Renvooi
Analytical Properties - Absorptance: 0.1; Roughness: 1
Graphics - Coarse Scale Fill Color: 8421504; Coarse Scale Fill Pattern: Solid fill
Identity Data - Assembly Code: 2C(27.0); Description: dak, generiek; Type Comments: d=200mm; Type Mark: 27-01

# IfcRoof: Basic Roof:27_RO_generiek_300, Basic Roof:27_RO_generiek_300:69826
In: 00_begane grond
Pset_RoofCommon - Reference: 27_RO_generiek_300; IsExternal: yes; TotalArea: 2.25 m2; ProjectedArea: 2.25 m2
Constraints - Base Level: Level: 00_begane grond; Base Offset From Level: 0 mm; Cutoff Offset: 0 mm; Related to Mass: no; Room Bounding: yes
Construction - Fascia Depth: 0 mm; Maximum Ridge Height: 300 mm; Rafter Cut: Plumb Cut; Default Thickness: 300 mm
Dimensions - Area: 2.25 m2; Thickness: 300 mm; Volume: 0.675 m3
Phasing - Phase Created: Renvooi
Analytical Properties - Absorptance: 0.1; Roughness: 1
Graphics - Coarse Scale Fill Color: 8421504; Coarse Scale Fill Pattern: Solid fill
Identity Data - Assembly Code: 2C(27.0); Description: dak, generiek; Type Comments: d=300mm; Type Mark: 27-02

# IfcRoof: Basic Roof:27_RO_hout_underlayment_189_171-18, Basic Roof:27_RO_hout_underlayment_189_171-18:69921
In: 00_begane grond
Pset_RoofCommon - Reference: 27_RO_hout_underlayment_189_171-18; IsExternal: yes; TotalArea: 2.25 m2; ProjectedArea: 2.25 m2
Constraints - Base Level: Level: 00_begane grond; Base Offset From Level: 0 mm; Cutoff Offset: 0 mm; Related to Mass: no; Room Bounding: yes
Construction - Fascia Depth: 0 mm; Maximum Ridge Height: 189 mm; Rafter Cut: Plumb Cut; Default Thickness: 189 mm
Dimensions - Area: 2.25 m2; Thickness: 189 mm; Volume: 0.42525 m3
Phasing - Phase Created: Renvooi
Analytical Properties - Absorptance: 0.1; Heat Transfer Coefficient (U): 5.02813; Roughness: 1; Thermal mass: 14315; Thermal Resistance (R): 0.198881
Graphics - Coarse Scale Fill Color: 8421504; Coarse Scale Fill Pattern: Solid fill
Identity Data - Assembly Code: 2B(27.20); Description: houten gordingen; Type Comments: underlayment beplating 18mm; Type Mark: 27-03

# IfcRoof: Basic Roof:47_RO_dakpan_grijs_300x300, Basic Roof:47_RO_dakpan_grijs_300x300:69939
In: 00_begane grond
Pset_RoofCommon - Reference: 47_RO_dakpan_grijs_300x300; IsExternal: yes; TotalArea: 2.25 m2; ProjectedArea: 2.25 m2
Constraints - Base Level: Level: 00_begane grond; Base Offset From Level: 0 mm; Cutoff Offset: 0 mm; Related to Mass: no; Room Bounding: yes
Construction - Fascia Depth: 0 mm; Maximum Ridge Height: 92 mm; Rafter Cut: Plumb Cut; Default Thickness: 92 mm
Dimensions - Area: 2.25 m2; Thickness: 92 mm; Volume: 0.207 m3
Phasing - Phase Created: Renvooi
Analytical Properties - Absorptance: 0.1; Heat Transfer Coefficient (U): 14.152; Roughness: 1; Thermal mass: 105803; Thermal Resistance (R): 0.0706616
Graphics - Coarse Scale Fill Color: 8421504; Coarse Scale Fill Pattern: Solid fill
Identity Data - Assembly Code: 2C(47.22); Description: dakpannen grijs op panlat; Type Mark: 47-03

# IfcRoof: Basic Roof:47_RO_dakpan_rood_300x300, Basic Roof:47_RO_dakpan_rood_300x300:69946
In: 00_begane grond
Pset_RoofCommon - Reference: 47_RO_dakpan_rood_300x300; IsExternal: yes; TotalArea: 2.25 m2; ProjectedArea: 2.25 m2
Constraints - Base Level: Level: 00_begane grond; Base Offset From Level: 0 mm; Cutoff Offset: 0 mm; Related to Mass: no; Room Bounding: yes
Construction - Fascia Depth: 0 mm; Maximum Ridge Height: 92 mm; Rafter Cut: Plumb Cut; Default Thickness: 92 mm
Dimensions - Area: 2.25 m2; Thickness: 92 mm; Volume: 0.207 m3
Phasing - Phase Created: Renvooi
Analytical Properties - Absorptance: 0.1; Heat Transfer Coefficient (U): 14.152; Roughness: 1; Thermal mass: 105803; Thermal Resistance (R): 0.0706616
Graphics - Coarse Scale Fill Color: 8421504; Coarse Scale Fill Pattern: Solid fill
Identity Data - Assembly Code: 2C(47.22); Description: dakpannen rood op panlat; Type Mark: 47-04

# IfcRoof: Basic Roof:47_RO_isolatie_EPS_bitumen_102_100-2, Basic Roof:47_RO_isolatie_EPS_bitumen_102_100-2:69892
In: 00_begane grond
Pset_RoofCommon - Reference: 47_RO_isolatie_EPS_bitumen_102_100-2; IsExternal: yes; TotalArea: 2.25 m2; ProjectedArea: 2.25 m2
Constraints - Base Level: Level: 00_begane grond; Base Offset From Level: 0 mm; Cutoff Offset: 0 mm; Related to Mass: no; Room Bounding: yes
Construction - Fascia Depth: 0 mm; Maximum Ridge Height: 102 mm; Rafter Cut: Plumb Cut; Default Thickness: 102 mm
Dimensions - Area: 2.25 m2; Thickness: 102 mm; Volume: 0.2295 m3
Phasing - Phase Created: Renvooi
Analytical Properties - Absorptance: 0.1; Heat Transfer Coefficient (U): 0.349787; Roughness: 1; Thermal mass: 7295.4; Thermal Resistance (R): 2.85888
Graphics - Coarse Scale Fill Color: 8421504; Coarse Scale Fill Pattern: Solid fill
Identity Data - Assembly Code: 2C(47.25); Description: EPS isolatie 100mm, beloopbaar; Type Comments: 2-laags bitumen; Type Mark: 47-02

# IfcRoof: Basic Roof:47_RO_isolatie_PIR_bitumen_82_80-2, Basic Roof:47_RO_isolatie_PIR_bitumen_82_80-2:69885
In: 00_begane grond
Pset_RoofCommon - Reference: 47_RO_isolatie_PIR_bitumen_82_80-2; IsExternal: yes; TotalArea: 2.25 m2; ProjectedArea: 2.25 m2
Constraints - Base Level: Level: 00_begane grond; Base Offset From Level: 0 mm; Cutoff Offset: 0 mm; Related to Mass: no; Room Bounding: yes
Construction - Fascia Depth: 0 mm; Maximum Ridge Height: 102 mm; Rafter Cut: Plumb Cut; Default Thickness: 102 mm
Dimensions - Area: 2.25 m2; Thickness: 102 mm; Volume: 0.2295 m3
Phasing - Phase Created: Renvooi
Analytical Properties - Absorptance: 0.1; Heat Transfer Coefficient (U): 0.299844; Roughness: 1; Thermal mass: 10529.4; Thermal Resistance (R): 3.33507
Graphics - Coarse Scale Fill Color: 8421504; Coarse Scale Fill Pattern: Solid fill
Identity Data - Assembly Code: 2C(47.21); Description: PIR isolatie 80mm; Type Comments: 2-laags bitumen; Type Mark: 47-01

# IfcRoof: Sloped Glazing:27_CW_SAB58KD_945mm, Sloped Glazing:27_CW_SAB58KD_945mm:165312
In: 00_begane grond
Type - Construction - Curtain Panel: 27_CWP_SAB58KD_945: SAB58KD_945; Join Condition: Not Defined
Type - Grid 1 - Adjust for Mullion Size: no; Layout: Fixed Distance; Spacing: 945 mm
Type - Grid 2 - Adjust for Mullion Size: no
Type - Identity Data - Assembly Code: 2C(47.20); Description: dakplaat SAB 58KD; Type Comments: plaatbreedte 945mm; Type Mark: 47-05
Pset_RoofCommon - Reference: 27_CW_SAB58KD_945mm; IsExternal: yes; ProjectedArea: 2.25 m2
Constraints - Base Level: Level: 00_begane grond; Base Offset From Level: 0 mm; Cutoff Offset: 0 mm; Related to Mass: no; Room Bounding: yes
Construction - Fascia Depth: 0 mm; Maximum Ridge Height: 100 mm; Rafter Cut: Plumb Cut
Dimensions - Thickness: 100 mm
Grid 1 - Angle: 0 deg; Justification: Beginning; Number: 4; Offset: 0 mm; sets with these values: 2
Phasing - Phase Created: Renvooi

# IfcSlab: Basic Roof:27_RO_dakplaat_enkelschalig_PIR_135_33-90-12, Basic Roof:27_RO_dakplaat_enkelschalig_PIR_135_33-90-12:69928
In: 00_begane grond
PredefinedType: ROOF; Material: 00_lucht_spouw_dak_geventileerd 33 mm, 20_isolatie_PIR 90 mm, 20_beplating_MDF 12 mm
Pset_SlabCommon - Reference: 27_RO_dakplaat_enkelschalig_PIR_135_33-90-12; IsExternal: yes; LoadBearing: yes; ThermalTransmittance: 0.321998 kg/K/s3; PitchAngle: 0 deg

# IfcSlab: Basic Roof:27_RO_dakplaat_sandwich_PIR_106_20-3-80-3, Basic Roof:27_RO_dakplaat_sandwich_PIR_106_20-3-80-3:77055
In: 00_begane grond
PredefinedType: ROOF; Material: 27_tengels_geventileerd 20 mm, 20_beplating_MDF 3 mm, 20_isolatie_PIR 80 mm, 20_beplating_MDF 3 mm
Pset_SlabCommon - Reference: 27_RO_dakplaat_sandwich_PIR_106_20-3-80-3; IsExternal: yes; LoadBearing: yes; ThermalTransmittance: 0.367638 kg/K/s3; PitchAngle: 0 deg

# IfcSlab: Basic Roof:27_RO_generiek_200, Basic Roof:27_RO_generiek_200:69710
In: 00_begane grond
PredefinedType: ROOF; Material: Default 200 mm
Pset_SlabCommon - Reference: 27_RO_generiek_200; IsExternal: yes; LoadBearing: yes; PitchAngle: 0 deg

# IfcSlab: Basic Roof:27_RO_generiek_300, Basic Roof:27_RO_generiek_300:69826
In: 00_begane grond
PredefinedType: ROOF; Material: Default 300 mm
Pset_SlabCommon - Reference: 27_RO_generiek_300; IsExternal: yes; LoadBearing: yes; PitchAngle: 0 deg

# IfcSlab: Basic Roof:27_RO_hout_underlayment_189_171-18, Basic Roof:27_RO_hout_underlayment_189_171-18:69921
In: 00_begane grond
PredefinedType: ROOF; Material: 27_beplating_underlayment 18 mm, 27_houten_balklaag_geventileerd 171 mm
Pset_SlabCommon - Reference: 27_RO_hout_underlayment_189_171-18; IsExternal: yes; LoadBearing: yes; ThermalTransmittance: 5.02813 kg/K/s3; PitchAngle: 0 deg

# IfcSlab: Basic Roof:47_RO_dakpan_grijs_300x300, Basic Roof:47_RO_dakpan_grijs_300x300:69939
In: 00_begane grond
PredefinedType: ROOF; Material: 47_dakpan_grijs 70 mm, 47_panlat_geventileerd 22 mm
Pset_SlabCommon - Reference: 47_RO_dakpan_grijs_300x300; IsExternal: yes; LoadBearing: yes; ThermalTransmittance: 14.152 kg/K/s3; PitchAngle: 0 deg

# IfcSlab: Basic Roof:47_RO_dakpan_rood_300x300, Basic Roof:47_RO_dakpan_rood_300x300:69946
In: 00_begane grond
PredefinedType: ROOF; Material: 47_dakpan_rood 70 mm, 47_panlat_geventileerd 22 mm
Pset_SlabCommon - Reference: 47_RO_dakpan_rood_300x300; IsExternal: yes; LoadBearing: yes; ThermalTransmittance: 14.152 kg/K/s3; PitchAngle: 0 deg

# IfcSlab: Basic Roof:47_RO_isolatie_EPS_bitumen_102_100-2, Basic Roof:47_RO_isolatie_EPS_bitumen_102_100-2:69892
In: 00_begane grond
PredefinedType: ROOF; Material: 47_bitumen 2 mm, 20_isolatie_EPS 100 mm
Pset_SlabCommon - Reference: 47_RO_isolatie_EPS_bitumen_102_100-2; IsExternal: yes; LoadBearing: yes; ThermalTransmittance: 0.349787 kg/K/s3; PitchAngle: 0 deg

# IfcSlab: Basic Roof:47_RO_isolatie_PIR_bitumen_82_80-2, Basic Roof:47_RO_isolatie_PIR_bitumen_82_80-2:69885
In: 00_begane grond
PredefinedType: ROOF; Material: 47_bitumen 2 mm, 20_isolatie_PIR 100 mm
Pset_SlabCommon - Reference: 47_RO_isolatie_PIR_bitumen_82_80-2; IsExternal: yes; LoadBearing: yes; ThermalTransmittance: 0.299844 kg/K/s3; PitchAngle: 0 deg

# IfcSlab: Floor:11_FL_werkvloer_stampbeton_50, Floor:11_FL_werkvloer_stampbeton_50:61065
In: 00_begane grond
PredefinedType: FLOOR; Material: 11_werkvloer_stampbeton 50 mm
Pset_SlabCommon - Reference: 11_FL_werkvloer_stampbeton_50; IsExternal: yes; LoadBearing: yes; Combustible: no; Compartmentation: no; ThermalTransmittance: 20.92 kg/K/s3; PitchAngle: 0 deg
Constraints - Height Offset From Level: 0 mm; Level: Level: 00_begane grond; Related to Mass: no; Room Bounding: yes
Dimensions - Area: 2.25 m2; Perimeter: 6000 mm; Thickness: 50 mm; Volume: 0.1125 m3
Fire Protection - brandwerend: no; ontvlambaar: no
Phasing - Phase Created: Renvooi
Structural - Enable Analytical Model: yes; Rebar Cover - Bottom Face: Rebar Cover Settings: Rebar Cover 1; Rebar Cover - Other Faces: Rebar Cover Settings: Rebar Cover 1; Rebar Cover - Top Face: Rebar Cover Settings: Rebar Cover 1; Structural: yes
Analytical Properties - Absorptance: 0.1; Heat Transfer Coefficient (U): 20.92; Roughness: 1; Thermal mass: 75555; Thermal Resistance (R): 0.0478011
Construction - Default Thickness: 50 mm; Function: Exterior
Graphics - Coarse Scale Fill Color: 8421504; Coarse Scale Fill Pattern: Solid fill
Identity Data - Assembly Code: 2A(13.11); Description: werkvloer, stampbeton; Keynote: d-16-000; Type Comments: d=50mm; Type Mark: 11-01
Materials and Finishes - Structural Material: 11_werkvloer_stampbeton

# IfcSlab: Floor:13_FL_generiek_100, Floor:13_FL_generiek_100:59713
In: 00_begane grond
PredefinedType: FLOOR; Material: Default 100 mm
Pset_SlabCommon - Reference: 13_FL_generiek_100; IsExternal: yes; LoadBearing: yes; Combustible: no; Compartmentation: no; PitchAngle: 0 deg
Constraints - Height Offset From Level: 0 mm; Level: Level: 00_begane grond; Related to Mass: no; Room Bounding: yes
Dimensions - Area: 2.25 m2; Perimeter: 6000 mm; Thickness: 100 mm; Volume: 0.225 m3
Fire Protection - brandwerend: no; ontvlambaar: no
Phasing - Phase Created: Renvooi
Structural - Enable Analytical Model: yes; Rebar Cover - Bottom Face: Rebar Cover Settings: Rebar Cover 1; Rebar Cover - Other Faces: Rebar Cover Settings: Rebar Cover 1; Rebar Cover - Top Face: Rebar Cover Settings: Rebar Cover 1; Structural: yes
Analytical Properties - Absorptance: 0.1; Roughness: 1
Construction - Default Thickness: 100 mm; Function: Exterior
Graphics - Coarse Scale Fill Color: 8421504; Coarse Scale Fill Pattern: Solid fill
Identity Data - Assembly Code: 2A(13.0); Description: vloer op grondslag, generiek; Keynote: d-23-000; Type Comments: d=100mm; Type Mark: 13-01
Materials and Finishes - Structural Material: Default

# IfcSlab: Floor:13_FL_ihwg_beton_geïsoleerd_222_120-100-2, Floor:13_FL_ihwg_beton_geïsoleerd_222_120-100-2:61277
In: 00_begane grond
PredefinedType: FLOOR; Material: 13_beton_ihwg_C20/25 120 mm, 20_isolatie_EPS 100 mm, 11_bodemafsluiter_folie 2 mm
Pset_SlabCommon - Reference: 13_FL_ihwg_beton_geïsoleerd_222_120-100-2; IsExternal: yes; LoadBearing: yes; Combustible: no; Compartmentation: no; ThermalTransmittance: 0.334856 kg/K/s3; PitchAngle: 0 deg
Constraints - Height Offset From Level: 0 mm; Level: Level: 00_begane grond; Related to Mass: no; Room Bounding: yes
Dimensions - Area: 2.25 m2; Perimeter: 6000 mm; Thickness: 222 mm; Volume: 0.4995 m3
Fire Protection - brandwerend: no; ontvlambaar: no
Phasing - Phase Created: Renvooi
Structural - Enable Analytical Model: yes; Rebar Cover - Bottom Face: Rebar Cover Settings: Rebar Cover 1; Rebar Cover - Other Faces: Rebar Cover Settings: Rebar Cover 1; Rebar Cover - Top Face: Rebar Cover Settings: Rebar Cover 1; Structural: yes
Analytical Properties - Absorptance: 0.1; Heat Transfer Coefficient (U): 0.334856; Roughness: 1; Thermal mass: 188604; Thermal Resistance (R): 2.98636
Construction - Default Thickness: 222 mm; Function: Exterior
Graphics - Coarse Scale Fill Color: 8421504; Coarse Scale Fill Pattern: Solid fill
Identity Data - Assembly Code: 2A(13.12); Description: 120mm in het werk gestorte betonvloer, klasse C20/25; Keynote: d-23-159; Type Comments: 100mm EPS, 2-laags vochtwerende folie; Type Mark: 13-02
Materials and Finishes - Structural Material: 13_beton_ihwg_C20/25

# IfcSlab: Floor:23_FL_breedplaat_50, Floor:23_FL_breedplaat_50:66030
In: 00_begane grond
PredefinedType: FLOOR; Material: layer 50 mm
Pset_SlabCommon - Reference: 23_FL_breedplaat_50; IsExternal: no; LoadBearing: yes; Combustible: no; Compartmentation: no; ThermalTransmittance: 20.92 kg/K/s3; PitchAngle: 0 deg
Constraints - Height Offset From Level: 0 mm; Level: Level: 00_begane grond; Related to Mass: no; Room Bounding: yes
Dimensions - Area: 2.25 m2; Perimeter: 6000 mm; Thickness: 50 mm; Volume: 0.1125 m3
Fire Protection - brandwerend: no; ontvlambaar: no
Phasing - Phase Created: Renvooi
Structural - Enable Analytical Model: yes; Rebar Cover - Bottom Face: Rebar Cover Settings: Rebar Cover 1; Rebar Cover - Other Faces: Rebar Cover Settings: Rebar Cover 1; Rebar Cover - Top Face: Rebar Cover Settings: Rebar Cover 1; Structural: yes
Analytical Properties - Absorptance: 0.1; Heat Transfer Coefficient (U): 20.92; Roughness: 1; Thermal mass: 75555; Thermal Resistance (R): 0.0478011
Construction - Default Thickness: 50 mm; Function: Interior
Graphics - Coarse Scale Fill Color: 8421504; Coarse Scale Fill Pattern: Solid fill
Identity Data - Assembly Code: 2B(23.21); Description: prefab breedplaatvloer, vrijdragend; Keynote: d-23-159; Type Comments: klasse C45, d = 50mm; Type Mark: 23-05

# IfcSlab: Floor:23_FL_breedplaat_60, Floor:23_FL_breedplaat_60:66037
In: 00_begane grond
PredefinedType: FLOOR; Material: layer 60 mm
Pset_SlabCommon - Reference: 23_FL_breedplaat_60; IsExternal: no; LoadBearing: yes; Combustible: no; Compartmentation: no; ThermalTransmittance: 17.4333 kg/K/s3; PitchAngle: 0 deg
Constraints - Height Offset From Level: 0 mm; Level: Level: 00_begane grond; Related to Mass: no; Room Bounding: yes
Dimensions - Area: 2.25 m2; Perimeter: 6000 mm; Thickness: 60 mm; Volume: 0.135 m3
Fire Protection - brandwerend: no; ontvlambaar: no
Phasing - Phase Created: Renvooi
Structural - Enable Analytical Model: yes; Rebar Cover - Bottom Face: Rebar Cover Settings: Rebar Cover 1; Rebar Cover - Other Faces: Rebar Cover Settings: Rebar Cover 1; Rebar Cover - Top Face: Rebar Cover Settings: Rebar Cover 1; Structural: yes
Analytical Properties - Absorptance: 0.1; Heat Transfer Coefficient (U): 17.4333; Roughness: 1; Thermal mass: 90666; Thermal Resistance (R): 0.0573614
Construction - Default Thickness: 60 mm; Function: Interior
Graphics - Coarse Scale Fill Color: 8421504; Coarse Scale Fill Pattern: Solid fill
Identity Data - Assembly Code: 2B(23.21); Description: prefab breedplaatvloer, vrijdragend; Keynote: d-23-159; Type Comments: klasse C45, d = 60mm; Type Mark: 23-06

# IfcSlab: Floor:23_FL_generiek_100, Floor:23_FL_generiek_100:60997
In: 00_begane grond
PredefinedType: FLOOR; Material: Default 100 mm
Pset_SlabCommon - Reference: 23_FL_generiek_100; IsExternal: yes; LoadBearing: yes; Combustible: no; Compartmentation: no; PitchAngle: 0 deg
Constraints - Height Offset From Level: 0 mm; Level: Level: 00_begane grond; Related to Mass: no; Room Bounding: yes
Dimensions - Area: 2.25 m2; Perimeter: 6000 mm; Thickness: 100 mm; Volume: 0.225 m3
Fire Protection - brandwerend: no; ontvlambaar: no
Phasing - Phase Created: Renvooi
Structural - Enable Analytical Model: yes; Rebar Cover - Bottom Face: Rebar Cover Settings: Rebar Cover 1; Rebar Cover - Other Faces: Rebar Cover Settings: Rebar Cover 1; Rebar Cover - Top Face: Rebar Cover Settings: Rebar Cover 1; Structural: yes
Analytical Properties - Absorptance: 0.1; Roughness: 1
Construction - Default Thickness: 100 mm; Function: Exterior
Graphics - Coarse Scale Fill Color: 8421504; Coarse Scale Fill Pattern: Solid fill
Identity Data - Assembly Code: 2B(23.20); Description: vloer, generiek; Keynote: d-23-000; Type Comments: d=100mm; Type Mark: 23-01
Materials and Finishes - Structural Material: Default

# IfcSlab: Floor:23_FL_generiek_300, Floor:23_FL_generiek_300:61057
In: 00_begane grond
PredefinedType: FLOOR; Material: Default 300 mm
Pset_SlabCommon - Reference: 23_FL_generiek_300; IsExternal: yes; LoadBearing: yes; Combustible: no; Compartmentation: no; PitchAngle: 0 deg
Constraints - Height Offset From Level: 0 mm; Level: Level: 00_begane grond; Related to Mass: no; Room Bounding: yes
Dimensions - Area: 2.25 m2; Perimeter: 6000 mm; Thickness: 300 mm; Volume: 0.675 m3
Fire Protection - brandwerend: no; ontvlambaar: no
Phasing - Phase Created: Renvooi
Structural - Enable Analytical Model: yes; Rebar Cover - Bottom Face: Rebar Cover Settings: Rebar Cover 1; Rebar Cover - Other Faces: Rebar Cover Settings: Rebar Cover 1; Rebar Cover - Top Face: Rebar Cover Settings: Rebar Cover 1; Structural: yes
Analytical Properties - Absorptance: 0.1; Roughness: 1
Construction - Default Thickness: 300 mm; Function: Exterior
Graphics - Coarse Scale Fill Color: 8421504; Coarse Scale Fill Pattern: Solid fill
Identity Data - Assembly Code: 2B(23.20); Description: vloer, generiek; Keynote: d-23-000; Type Comments: d=300mm; Type Mark: 23-02
Materials and Finishes - Structural Material: Default

# IfcSlab: Floor:23_FL_hout_underlayment_189mm_171-18, Floor:23_FL_hout_underlayment_189mm_171-18:66078
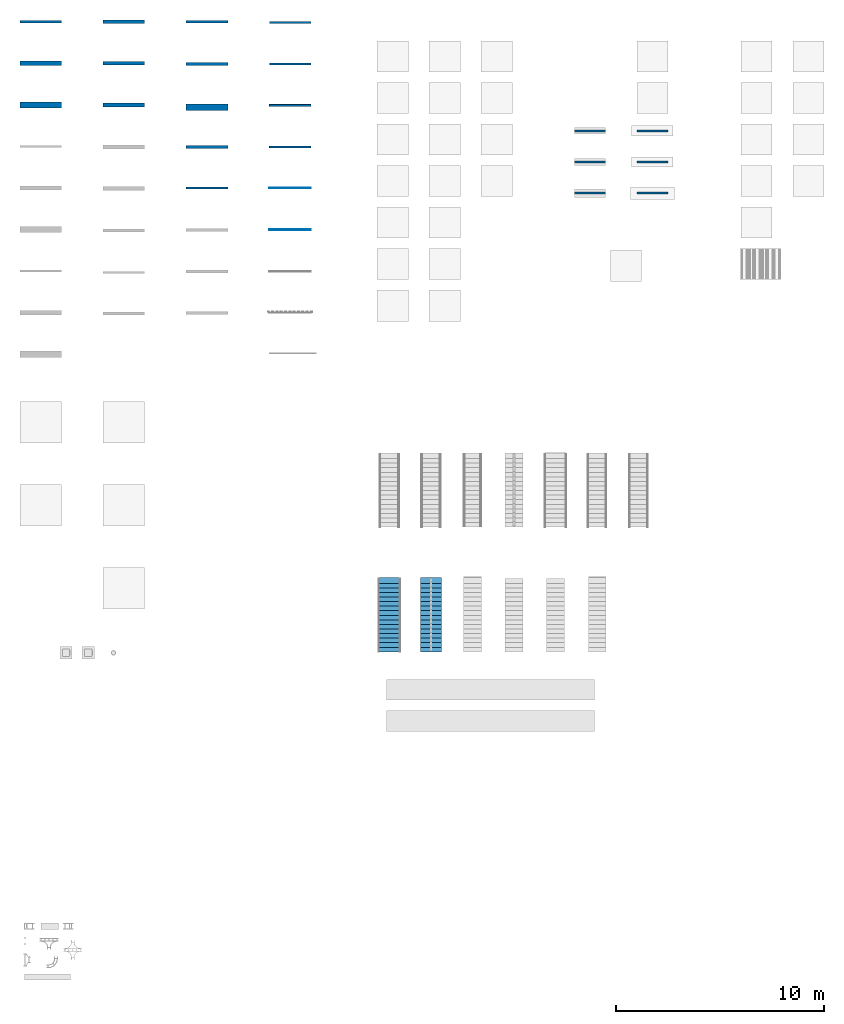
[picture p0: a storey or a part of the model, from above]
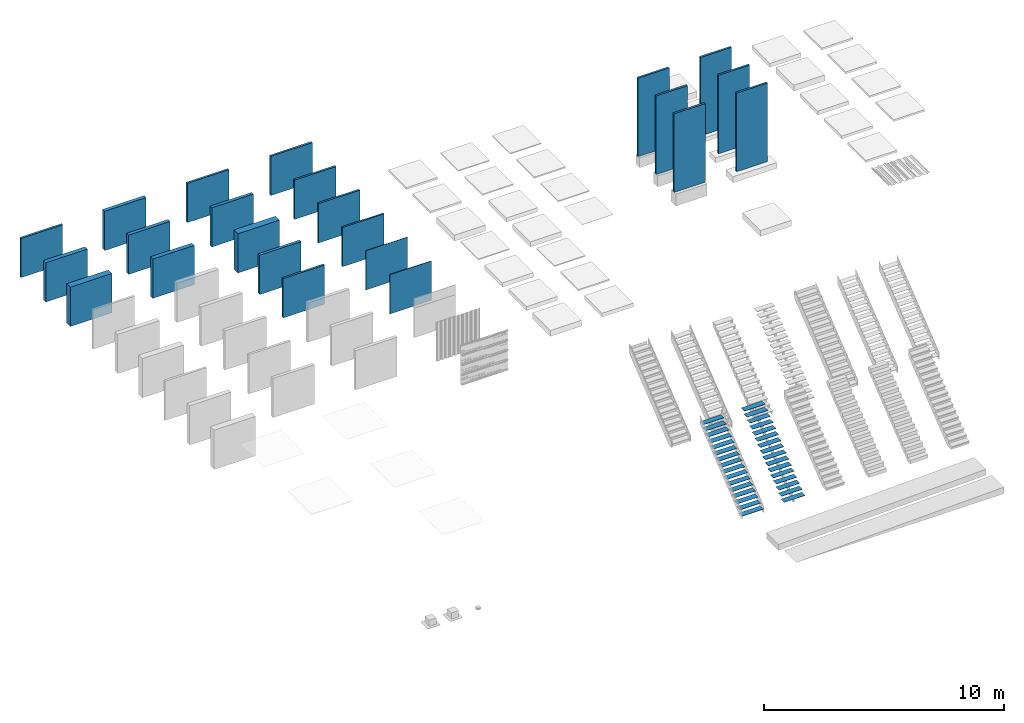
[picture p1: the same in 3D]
Properties of the parts of a building model (IFC2X3), part 2 of 3

# IfcSlab: Floor:23_FL_hout_underlayment_189mm_171-18, Floor:23_FL_hout_underlayment_189mm_171-18:66078
In: 00_begane grond
PredefinedType: FLOOR; Material: 23_beplating_underlayment 18 mm, 23_houten_balklaag_geventileerd 171 mm
Pset_SlabCommon - Reference: 23_FL_hout_underlayment_189mm_171-18; IsExternal: no; LoadBearing: yes; Combustible: no; Compartmentation: no; ThermalTransmittance: 5.02813 kg/K/s3; PitchAngle: 0 deg
Constraints - Height Offset From Level: 0 mm; Level: Level: 00_begane grond; Related to Mass: no; Room Bounding: yes
Dimensions - Area: 2.25 m2; Perimeter: 6000 mm; Thickness: 189 mm; Volume: 0.42525 m3
Fire Protection - brandwerend: no; ontvlambaar: no
Phasing - Phase Created: Renvooi
Structural - Enable Analytical Model: yes; Rebar Cover - Bottom Face: Rebar Cover Settings: Rebar Cover 1; Rebar Cover - Other Faces: Rebar Cover Settings: Rebar Cover 1; Rebar Cover - Top Face: Rebar Cover Settings: Rebar Cover 1; Structural: yes
Analytical Properties - Absorptance: 0.1; Heat Transfer Coefficient (U): 5.02813; Roughness: 1; Thermal mass: 14315; Thermal Resistance (R): 0.198881
Construction - Default Thickness: 189 mm; Function: Interior
Graphics - Coarse Scale Fill Color: 8421504; Coarse Scale Fill Pattern: Solid fill
Identity Data - Assembly Code: 2B(23.21); Description: houten balklaag, h = 171mm, vrijdragend; Keynote: d-23-000; Type Comments: 18mm underlayment, mechanisch bevestigd; Type Mark: 23-11

# IfcSlab: Floor:23_FL_ihwg_beton_200, Floor:23_FL_ihwg_beton_200:61401
In: 00_begane grond
PredefinedType: FLOOR; Material: 13_beton_ihwg_C20/25 200 mm
Pset_SlabCommon - Reference: 23_FL_ihwg_beton_200; IsExternal: no; LoadBearing: yes; Combustible: no; Compartmentation: no; ThermalTransmittance: 5.23 kg/K/s3; PitchAngle: 0 deg
Constraints - Height Offset From Level: 0 mm; Level: Level: 00_begane grond; Related to Mass: no; Room Bounding: yes
Dimensions - Area: 2.25 m2; Perimeter: 6000 mm; Thickness: 200 mm; Volume: 0.45 m3
Fire Protection - brandwerend: no; ontvlambaar: no
Phasing - Phase Created: Renvooi
Structural - Enable Analytical Model: yes; Rebar Cover - Bottom Face: Rebar Cover Settings: Rebar Cover 1; Rebar Cover - Other Faces: Rebar Cover Settings: Rebar Cover 1; Rebar Cover - Top Face: Rebar Cover Settings: Rebar Cover 1; Structural: yes
Analytical Properties - Absorptance: 0.1; Heat Transfer Coefficient (U): 5.23; Roughness: 1; Thermal mass: 302220; Thermal Resistance (R): 0.191205
Construction - Default Thickness: 200 mm; Function: Interior
Graphics - Coarse Scale Fill Color: 8421504; Coarse Scale Fill Pattern: Solid fill
Identity Data - Assembly Code: 2B(23.21); Description: in het werk gestorte betonvloer, vrijdragend; Keynote: d-23-156; Type Comments: klasse C20/25, d = 200mm; Type Mark: 23-03
Materials and Finishes - Structural Material: 13_beton_ihwg_C20/25

# IfcSlab: Floor:23_FL_ihwg_beton_300, Floor:23_FL_ihwg_beton_300:61560
In: 00_begane grond
PredefinedType: FLOOR; Material: 13_beton_ihwg_C20/25 300 mm
Pset_SlabCommon - Reference: 23_FL_ihwg_beton_300; IsExternal: no; LoadBearing: yes; Combustible: no; Compartmentation: no; ThermalTransmittance: 3.48667 kg/K/s3; PitchAngle: 0 deg
Constraints - Height Offset From Level: 0 mm; Level: Level: 00_begane grond; Related to Mass: no; Room Bounding: yes
Dimensions - Area: 2.25 m2; Perimeter: 6000 mm; Thickness: 300 mm; Volume: 0.675 m3
Fire Protection - brandwerend: no; ontvlambaar: no
Phasing - Phase Created: Renvooi
Structural - Enable Analytical Model: yes; Rebar Cover - Bottom Face: Rebar Cover Settings: Rebar Cover 1; Rebar Cover - Other Faces: Rebar Cover Settings: Rebar Cover 1; Rebar Cover - Top Face: Rebar Cover Settings: Rebar Cover 1; Structural: yes
Analytical Properties - Absorptance: 0.1; Heat Transfer Coefficient (U): 3.48667; Roughness: 1; Thermal mass: 453330; Thermal Resistance (R): 0.286807
Construction - Default Thickness: 300 mm; Function: Interior
Graphics - Coarse Scale Fill Color: 8421504; Coarse Scale Fill Pattern: Solid fill
Identity Data - Assembly Code: 2B(23.21); Description: in het werk gestorte betonvloer, vrijdragend; Keynote: d-23-156; Type Comments: klasse C20/25, d = 300mm; Type Mark: 23-04
Materials and Finishes - Structural Material: 13_beton_ihwg_C20/25

# IfcSlab: Floor:23_FL_kanaalplaat_200, Floor:23_FL_kanaalplaat_200:66044
In: 00_begane grond
PredefinedType: FLOOR; Material: layer 200 mm
Pset_SlabCommon - Reference: 23_FL_kanaalplaat_200; IsExternal: no; LoadBearing: yes; Combustible: no; Compartmentation: no; ThermalTransmittance: 5.23 kg/K/s3; PitchAngle: 0 deg
Constraints - Height Offset From Level: 0 mm; Level: Level: 00_begane grond; Related to Mass: no; Room Bounding: yes
Dimensions - Area: 2.25 m2; Perimeter: 6000 mm; Thickness: 200 mm; Volume: 0.45 m3
Fire Protection - brandwerend: no; ontvlambaar: no
Phasing - Phase Created: Renvooi
Structural - Enable Analytical Model: yes; Rebar Cover - Bottom Face: Rebar Cover Settings: Rebar Cover 1; Rebar Cover - Other Faces: Rebar Cover Settings: Rebar Cover 1; Rebar Cover - Top Face: Rebar Cover Settings: Rebar Cover 1; Structural: yes
Analytical Properties - Absorptance: 0.1; Heat Transfer Coefficient (U): 5.23; Roughness: 1; Thermal mass: 302220; Thermal Resistance (R): 0.191205
Construction - Default Thickness: 200 mm; Function: Interior
Graphics - Coarse Scale Fill Color: 8421504; Coarse Scale Fill Pattern: Solid fill
Identity Data - Assembly Code: 2B(23.21); Description: prefab kanaalplaatvloer, vrijdragend; Keynote: d-23-051; Type Comments: klasse C45, d = 200mm; Type Mark: 23-07

# IfcSlab: Floor:23_FL_kanaalplaat_260, Floor:23_FL_kanaalplaat_260:66051
In: 00_begane grond
PredefinedType: FLOOR; Material: layer 260 mm
Pset_SlabCommon - Reference: 23_FL_kanaalplaat_260; IsExternal: no; LoadBearing: yes; Combustible: no; Compartmentation: no; ThermalTransmittance: 4.02308 kg/K/s3; PitchAngle: 0 deg
Constraints - Height Offset From Level: 0 mm; Level: Level: 00_begane grond; Related to Mass: no; Room Bounding: yes
Dimensions - Area: 2.25 m2; Perimeter: 6000 mm; Thickness: 260 mm; Volume: 0.585 m3
Fire Protection - brandwerend: no; ontvlambaar: no
Phasing - Phase Created: Renvooi
Structural - Enable Analytical Model: yes; Rebar Cover - Bottom Face: Rebar Cover Settings: Rebar Cover 1; Rebar Cover - Other Faces: Rebar Cover Settings: Rebar Cover 1; Rebar Cover - Top Face: Rebar Cover Settings: Rebar Cover 1; Structural: yes
Analytical Properties - Absorptance: 0.1; Heat Transfer Coefficient (U): 4.02308; Roughness: 1; Thermal mass: 392886; Thermal Resistance (R): 0.248566
Construction - Default Thickness: 260 mm; Function: Interior
Graphics - Coarse Scale Fill Color: 8421504; Coarse Scale Fill Pattern: Solid fill
Identity Data - Assembly Code: 2B(23.21); Description: prefab kanaalplaatvloer, vrijdragend; Keynote: d-23-051; Type Comments: klasse C45, d = 260mm; Type Mark: 23-08

# IfcSlab: Floor:23_FL_zwaluwstaartvloer_ihwg_beton_50, Floor:23_FL_zwaluwstaartvloer_ihwg_beton_50:66058
In: 00_begane grond
PredefinedType: FLOOR; Material: 13_beton_ihwg_C20/25 50 mm
Pset_SlabCommon - Reference: 23_FL_zwaluwstaartvloer_ihwg_beton_50; IsExternal: no; LoadBearing: yes; Combustible: no; Compartmentation: no; ThermalTransmittance: 20.92 kg/K/s3; PitchAngle: 0 deg
Constraints - Height Offset From Level: 0 mm; Level: Level: 00_begane grond; Related to Mass: no; Room Bounding: yes
Dimensions - Area: 2.25 m2; Perimeter: 6000 mm; Thickness: 50 mm; Volume: 0.1125 m3
Fire Protection - brandwerend: no; ontvlambaar: no
Phasing - Phase Created: Renvooi
Structural - Enable Analytical Model: yes; Rebar Cover - Bottom Face: Rebar Cover Settings: Rebar Cover 1; Rebar Cover - Other Faces: Rebar Cover Settings: Rebar Cover 1; Rebar Cover - Top Face: Rebar Cover Settings: Rebar Cover 1; Structural: yes
Analytical Properties - Absorptance: 0.1; Heat Transfer Coefficient (U): 20.92; Roughness: 1; Thermal mass: 75555; Thermal Resistance (R): 0.0478011
Construction - Default Thickness: 50 mm; Function: Interior
Graphics - Coarse Scale Fill Color: 8421504; Coarse Scale Fill Pattern: Solid fill
Identity Data - Assembly Code: 2B(23.21); Description: zwaluwstaarvloer, plaatdikte 0,8mm; Keynote: d-23-116; Type Comments: in het werk gestort beton, klasse C25, d = 50mm; Type Mark: 23-09
Materials and Finishes - Structural Material: 13_beton_ihwg_C20/25

# IfcSlab: Floor:23_FL_zwaluwstaartvloer_ihwg_beton_75, Floor:23_FL_zwaluwstaartvloer_ihwg_beton_75:66070
In: 00_begane grond
PredefinedType: FLOOR; Material: 13_beton_ihwg_C20/25 75 mm
Pset_SlabCommon - Reference: 23_FL_zwaluwstaartvloer_ihwg_beton_75; IsExternal: no; LoadBearing: yes; Combustible: no; Compartmentation: no; ThermalTransmittance: 13.9467 kg/K/s3; PitchAngle: 0 deg
Constraints - Height Offset From Level: 0 mm; Level: Level: 00_begane grond; Related to Mass: no; Room Bounding: yes
Dimensions - Area: 2.25 m2; Perimeter: 6000 mm; Thickness: 75 mm; Volume: 0.16875 m3
Fire Protection - brandwerend: no; ontvlambaar: no
Phasing - Phase Created: Renvooi
Structural - Enable Analytical Model: yes; Rebar Cover - Bottom Face: Rebar Cover Settings: Rebar Cover 1; Rebar Cover - Other Faces: Rebar Cover Settings: Rebar Cover 1; Rebar Cover - Top Face: Rebar Cover Settings: Rebar Cover 1; Structural: yes
Analytical Properties - Absorptance: 0.1; Heat Transfer Coefficient (U): 13.9467; Roughness: 1; Thermal mass: 113332; Thermal Resistance (R): 0.0717017
Construction - Default Thickness: 75 mm; Function: Interior
Graphics - Coarse Scale Fill Color: 8421504; Coarse Scale Fill Pattern: Solid fill
Identity Data - Assembly Code: 2B(23.21); Description: zwaluwstaarvloer, plaatdikte 0,8mm; Keynote: d-23-116; Type Comments: in het werk gestort beton, klasse C25, d = 75mm; Type Mark: 23-10
Materials and Finishes - Structural Material: 13_beton_ihwg_C20/25

# IfcSlab: Floor:43_FL_cementdekvloer_50, Floor:43_FL_cementdekvloer_50:67492
In: 00_begane grond
PredefinedType: FLOOR; Material: 43_dekvloer_zandcement 50 mm
Pset_SlabCommon - Reference: 43_FL_cementdekvloer_50; IsExternal: no; LoadBearing: no; Combustible: no; Compartmentation: no; ThermalTransmittance: 20.92 kg/K/s3; PitchAngle: 0 deg
Constraints - Height Offset From Level: 0 mm; Level: Level: 00_begane grond; Related to Mass: no; Room Bounding: yes
Dimensions - Area: 2.25 m2; Perimeter: 6000 mm; Thickness: 50 mm; Volume: 0.1125 m3
Fire Protection - brandwerend: no; ontvlambaar: no
Phasing - Phase Created: Renvooi
Structural - Enable Analytical Model: no; Structural: no
Analytical Properties - Absorptance: 0.1; Heat Transfer Coefficient (U): 20.92; Roughness: 1; Thermal mass: 75555; Thermal Resistance (R): 0.0478011
Construction - Default Thickness: 50 mm; Function: Interior
Graphics - Coarse Scale Fill Color: 8421504; Coarse Scale Fill Pattern: Solid fill
Identity Data - Assembly Code: 2F(43.21); Description: zandcement dekvloer; Keynote: d-43-000; Type Comments: d = 50mm; Type Mark: 43-01

# IfcSlab: Floor:43_FL_cementdekvloer_70, Floor:43_FL_cementdekvloer_70:67499
In: 00_begane grond
PredefinedType: FLOOR; Material: 43_dekvloer_zandcement 70 mm
Pset_SlabCommon - Reference: 43_FL_cementdekvloer_70; IsExternal: no; LoadBearing: no; Combustible: no; Compartmentation: no; ThermalTransmittance: 14.9429 kg/K/s3; PitchAngle: 0 deg
Constraints - Height Offset From Level: 0 mm; Level: Level: 00_begane grond; Related to Mass: no; Room Bounding: yes
Dimensions - Area: 2.25 m2; Perimeter: 6000 mm; Thickness: 70 mm; Volume: 0.1575 m3
Fire Protection - brandwerend: no; ontvlambaar: no
Phasing - Phase Created: Renvooi
Structural - Enable Analytical Model: no; Structural: no
Analytical Properties - Absorptance: 0.1; Heat Transfer Coefficient (U): 14.9429; Roughness: 1; Thermal mass: 105777; Thermal Resistance (R): 0.0669216
Construction - Default Thickness: 70 mm; Function: Interior
Graphics - Coarse Scale Fill Color: 8421504; Coarse Scale Fill Pattern: Solid fill
Identity Data - Assembly Code: 2F(43.21); Description: zandcement dekvloer; Keynote: d-43-000; Type Comments: d = 70mm; Type Mark: 43-02

# IfcSlab: Floor:43_FL_eiken_planken 150_geluidsisolatie_52_22-30, Floor:43_FL_eiken_planken 150_geluidsisolatie_52_22-30:67506
In: 00_begane grond
PredefinedType: FLOOR; Material: 43_vloerafwerking_hout_planken 22 mm, 20_isolatie_steenwol 30 mm
Pset_SlabCommon - Reference: 43_FL_eiken_planken 150_geluidsisolatie_52_22-30; IsExternal: no; LoadBearing: no; Combustible: no; Compartmentation: no; ThermalTransmittance: 0.995446 kg/K/s3; PitchAngle: 0 deg
Constraints - Height Offset From Level: 0 mm; Level: Level: 00_begane grond; Related to Mass: no; Room Bounding: yes
Dimensions - Area: 2.25 m2; Perimeter: 6000 mm; Thickness: 52 mm; Volume: 0.117 m3
Fire Protection - brandwerend: no; ontvlambaar: no
Phasing - Phase Created: Renvooi
Structural - Enable Analytical Model: no; Structural: no
Analytical Properties - Absorptance: 0.1; Heat Transfer Coefficient (U): 0.995446; Roughness: 1; Thermal mass: 37316.1; Thermal Resistance (R): 1.00458
Construction - Default Thickness: 52 mm; Function: Interior
Graphics - Coarse Scale Fill Color: 8421504; Coarse Scale Fill Pattern: Solid fill
Identity Data - Assembly Code: 2F(43.22); Description: houten planken 150x22mm, zwevend aangebracht; Keynote: d-43-000; Type Comments: op 30mm geluidwerende isolatie; Type Mark: 43-03

# IfcSlab: Floor:43_FL_tapijt_rood, Floor:43_FL_tapijt_rood:67513
In: 00_begane grond
PredefinedType: FLOOR; Material: 43_tapijt_rood 9 mm
Pset_SlabCommon - Reference: 43_FL_tapijt_rood; IsExternal: no; LoadBearing: no; Combustible: no; Compartmentation: no; ThermalTransmittance: 6.66667 kg/K/s3; PitchAngle: 0 deg
Constraints - Height Offset From Level: 0 mm; Level: Level: 00_begane grond; Related to Mass: no; Room Bounding: yes
Dimensions - Area: 2.25 m2; Perimeter: 6000 mm; Thickness: 9 mm; Volume: 0.02025 m3
Fire Protection - brandwerend: no; ontvlambaar: no
Phasing - Phase Created: Renvooi
Structural - Enable Analytical Model: no; Structural: no
Analytical Properties - Absorptance: 0.1; Heat Transfer Coefficient (U): 6.66667; Roughness: 1; Thermal mass: 2325.6; Thermal Resistance (R): 0.15
Construction - Default Thickness: 9 mm; Function: Interior
Graphics - Coarse Scale Fill Color: 8421504; Coarse Scale Fill Pattern: Solid fill
Identity Data - Assembly Code: 2F(43.22); Description: tapijt, rood, 9mm dik; Keynote: d-43-003; Type Mark: 43-04

# IfcSlab: Pad:90_SITE_bouwplaats, Pad:90_SITE_bouwplaats:79251
In: 00_begane grond
PredefinedType: FLOOR; Material: 90_bouwplaats 300 mm
Pset_SlabCommon - Reference: 90_SITE_bouwplaats; IsExternal: no; LoadBearing: yes
Constraints - Height Offset From Level: 0 mm; Level: Level: 00_begane grond; Room Bounding: yes
Dimensions - Area: 2.25 m2; Perimeter: 6000 mm; Volume: 0.675 m3
Phasing - Phase Created: Renvooi
Graphics - Coarse Scale Fill Color: 8421504; Coarse Scale Fill Pattern: Solid fill
Construction - Thickness: 300 mm
Analytical Properties - Absorptance: 0.1; Roughness: 1

# IfcStair: Assembled Stair:24_ST_houten trap_gesloten_b=850_op=185_aan=220:49186, Assembled Stair:Stair:68679
In: 00_begane grond
Pset_StairCommon - Reference: 24_ST_houten trap_gesloten_b=850_op=185_aan=220; IsExternal: no; NumberOfRiser: 17; NumberOfTreads: 16; RiserHeight: 53788.2 mm; TreadLength: 220 mm; HandicapAccessible: no; FireExit: no; HasNonSkidSurface: no
Constraints - Base Level: Level: 00_begane grond; Base Offset: 0 mm; Desired Stair Height: 3000 mm; Top Level: Level: 01_eerste verdieping; Top Offset: 0 mm
Dimensions - Actual Number of Risers: 17; Actual Riser Height: 176.471 mm; Actual Tread Depth: 220 mm; Desired Number of Risers: 17; Tread/Riser Start Number: 1
Fire Protection - brandwerend: no; ontvlambaar: no
Identity Data - antislip: no; toegankelijk: no; vluchtweg: no; Assembly Code: 2G(24.10); Description: houten trap, gesloten, b=850mm; Keynote: d-24-000; Type Comments: max optrede 185mm, min aantrede 220mm; Type Mark: 24-01
Phasing - Phase Created: Renvooi
Calculation Rules - Maximum Riser Height: 185 mm; Minimum Run Width: 850 mm; Minimum Tread Depth: 220 mm
Construction - Function: Interior; Landing Type: Non-Monolithic Landing: 24_STL_bordes_niet-monolitisch_hout; Run Type: Non-Monolithic Run: 24_STR_trede_hout_vuren_40_neus_50_stootbord_10
Graphics - Cut Mark Type: Stair Cut Mark: 24_STCM_enkele snede
Supports - Left Lateral Offset: 0 mm; Left Support: Stringer (Closed); Left Support Type: Stringer: 24_STS_trapboom_hout_vuren_45x50; Middle Support: no; Middle Support Number: 0; Right Lateral Offset: 0 mm; Right Support: Stringer (Closed); Right Support Type: Stringer: 24_STS_trapboom_hout_vuren_45x50

# IfcStair: Assembled Stair:24_ST_houten trap_open_b=850_op=185_aan=220:49184, Assembled Stair:Stair:68953
In: 00_begane grond
Pset_StairCommon - Reference: 24_ST_houten trap_open_b=850_op=185_aan=220; IsExternal: no; NumberOfRiser: 17; NumberOfTreads: 16; RiserHeight: 53788.2 mm; TreadLength: 220 mm; HandicapAccessible: no; FireExit: no; HasNonSkidSurface: no
Constraints - Base Level: Level: 00_begane grond; Base Offset: 0 mm; Desired Stair Height: 3000 mm; Top Level: Level: 01_eerste verdieping; Top Offset: 0 mm
Dimensions - Actual Number of Risers: 17; Actual Riser Height: 176.471 mm; Actual Tread Depth: 220 mm; Desired Number of Risers: 17; Tread/Riser Start Number: 1; vrije_hoogte: 0 mm
Fire Protection - brandwerend: no; ontvlambaar: no
Identity Data - antislip: no; toegankelijk: no; vluchtweg: no; Assembly Code: 2G(24.10); Description: houten trap, open, b=850mm; Keynote: d-24-000; Type Comments: max optrede 185mm, min aantrede 220mm; Type Mark: 24-02
Phasing - Phase Created: Renvooi
Calculation Rules - Maximum Riser Height: 185 mm; Minimum Run Width: 850 mm; Minimum Tread Depth: 220 mm
Construction - Function: Interior; Landing Type: Non-Monolithic Landing: 24_STL_bordes_niet-monolitisch_hout; Run Type: Non-Monolithic Run: 24_STR_trede_hout_vuren_40_neus_50
Graphics - Cut Mark Type: Stair Cut Mark: 24_STCM_enkele snede
Supports - Left Lateral Offset: 0 mm; Left Support: Stringer (Closed); Left Support Type: Stringer: 24_STS_trapboom_hout_vuren_45x50; Middle Support: no; Middle Support Number: 0; Right Lateral Offset: 0 mm; Right Support: Stringer (Closed); Right Support Type: Stringer: 24_STS_trapboom_hout_vuren_45x50

# IfcStair: Assembled Stair:24_ST_houten trap_open_gezadeld_b=850_op=185_aan=220:49189, Assembled Stair:Stair:69257
In: 00_begane grond
Pset_StairCommon - Reference: 24_ST_houten trap_open_gezadeld_b=850_op=185_aan=220; IsExternal: no; NumberOfRiser: 17; NumberOfTreads: 16; RiserHeight: 53788.2 mm; TreadLength: 220 mm; HandicapAccessible: no; FireExit: no; HasNonSkidSurface: no
Constraints - Base Level: Level: 00_begane grond; Base Offset: 0 mm; Desired Stair Height: 3000 mm; Top Level: Level: 01_eerste verdieping; Top Offset: 0 mm
Dimensions - Actual Number of Risers: 17; Actual Riser Height: 176.471 mm; Actual Tread Depth: 220 mm; Desired Number of Risers: 17; Tread/Riser Start Number: 1
Fire Protection - brandwerend: no; ontvlambaar: no
Identity Data - antislip: no; toegankelijk: no; vluchtweg: no; Assembly Code: 2G(24.10); Description: houten trap, openn, gezadeld, b=850mm; Keynote: d-24-000; Type Comments: max optrede 185mm, min aantrede 220mm; Type Mark: 24-03
Phasing - Phase Created: Renvooi
Calculation Rules - Maximum Riser Height: 185 mm; Minimum Run Width: 850 mm; Minimum Tread Depth: 220 mm
Construction - Function: Interior; Landing Type: Non-Monolithic Landing: 24_STL_bordes_niet-monolitisch_hout; Run Type: Non-Monolithic Run: 24_STR_trede_hout_vuren_40_neus_50
Graphics - Cut Mark Type: Stair Cut Mark: 24_STCM_enkele snede
Supports - Left Lateral Offset: 0 mm; Left Support: Carriage (Open); Left Support Type: Carriage: 24_STC_middenboom_hout_vuren_45x100; Middle Support: no; Middle Support Number: 0; Right Lateral Offset: 0 mm; Right Support: Carriage (Open); Right Support Type: Carriage: 24_STC_middenboom_hout_vuren_45x100

# IfcStair: Assembled Stair:24_ST_houten trap_open_middenboom_b=850_op=185_aan=220:49181, Assembled Stair:Stair:69261
In: 00_begane grond
Pset_StairCommon - Reference: 24_ST_houten trap_open_middenboom_b=850_op=185_aan=220; IsExternal: no; NumberOfRiser: 17; NumberOfTreads: 16; RiserHeight: 53788.2 mm; TreadLength: 220 mm; HandicapAccessible: no; FireExit: no; HasNonSkidSurface: no
Constraints - Base Level: Level: 00_begane grond; Base Offset: 0 mm; Desired Stair Height: 3000 mm; Top Level: Level: 01_eerste verdieping; Top Offset: 0 mm
Dimensions - Actual Number of Risers: 17; Actual Riser Height: 176.471 mm; Actual Tread Depth: 220 mm; Desired Number of Risers: 17; Tread/Riser Start Number: 1
Fire Protection - brandwerend: no; ontvlambaar: no
Identity Data - antislip: no; toegankelijk: no; vluchtweg: no; Assembly Code: 2G(24.10); Description: houten trap, open, met middenboom, b=850mm; Keynote: d-24-000; Type Comments: max optrede 185mm, min aantrede 220mm; Type Mark: 24-04
Phasing - Phase Created: Renvooi
Calculation Rules - Maximum Riser Height: 185 mm; Minimum Run Width: 850 mm; Minimum Tread Depth: 220 mm
Construction - Function: Interior; Landing Type: Non-Monolithic Landing: 24_STL_bordes_niet-monolitisch_hout; Run Type: Non-Monolithic Run: 24_STR_trede_hout_vuren_40_neus_50
Graphics - Cut Mark Type: Stair Cut Mark: 24_STCM_enkele snede
Supports - Left Lateral Offset: 0 mm; Middle Support: yes; Middle Support Number: 1; Middle Support Type: Carriage: 24_STC_middenboom_hout_vuren_100x50; Right Lateral Offset: 0 mm

# IfcStair: Assembled Stair:24_ST_stalen trap_gesloten_b=1000_op=185_aan=220:49174, Assembled Stair:Stair:69280
In: 00_begane grond
Pset_StairCommon - Reference: 24_ST_stalen trap_gesloten_b=1000_op=185_aan=220; IsExternal: no; NumberOfRiser: 17; NumberOfTreads: 16; RiserHeight: 53788.2 mm; TreadLength: 220 mm; HandicapAccessible: no; FireExit: no; HasNonSkidSurface: no
Constraints - Base Level: Level: 00_begane grond; Base Offset: 0 mm; Desired Stair Height: 3000 mm; Top Level: Level: 01_eerste verdieping; Top Offset: 0 mm
Dimensions - Actual Number of Risers: 17; Actual Riser Height: 176.471 mm; Actual Tread Depth: 220 mm; Desired Number of Risers: 17; Tread/Riser Start Number: 1
Fire Protection - brandwerend: no; ontvlambaar: no
Identity Data - antislip: no; toegankelijk: no; vluchtweg: no; Assembly Code: 2G(24.10); Description: stalen trap, met stootbord, b=1000mm; Keynote: d-24-000; Type Comments: max optrede 185mm, min aantrede 220mm; Type Mark: 24-05
Phasing - Phase Created: Renvooi
Calculation Rules - Maximum Riser Height: 185 mm; Minimum Run Width: 1000 mm; Minimum Tread Depth: 220 mm
Construction - Function: Interior; Landing Type: Non-Monolithic Landing: 24_STL_bordes_niet-monolitisch_hout; Run Type: Non-Monolithic Run: 24_STR_trede_staal_gegalvaniseerd_rooster_15_neus_50_stootbord_15
Graphics - Cut Mark Type: Stair Cut Mark: 24_STCM_enkele snede
Supports - Left Lateral Offset: 0 mm; Left Support: Stringer (Closed); Left Support Type: Stringer: 24_STS_trapboom_hout_vuren_15x50; Middle Support: no; Middle Support Number: 0; Right Lateral Offset: 0 mm; Right Support: Stringer (Closed); Right Support Type: Stringer: 24_STS_trapboom_hout_vuren_15x50

# IfcStair: Assembled Stair:24_ST_stalen trap_open_b=1000_op=185_aan=350:49191, Assembled Stair:Stair:69305
In: 00_begane grond
Pset_StairCommon - Reference: 24_ST_stalen trap_open_b=1000_op=185_aan=350; IsExternal: no; NumberOfRiser: 17; NumberOfTreads: 16; RiserHeight: 53788.2 mm; TreadLength: 220 mm; HandicapAccessible: no; FireExit: no; HasNonSkidSurface: no
Constraints - Base Level: Level: 00_begane grond; Base Offset: 0 mm; Desired Stair Height: 3000 mm; Top Level: Level: 01_eerste verdieping; Top Offset: 0 mm
Dimensions - Actual Number of Risers: 17; Actual Riser Height: 176.471 mm; Actual Tread Depth: 220 mm; Desired Number of Risers: 17; Tread/Riser Start Number: 1
Fire Protection - brandwerend: no; ontvlambaar: no
Identity Data - antislip: no; toegankelijk: no; vluchtweg: no; Assembly Code: 2G(24.1); Description: stalen trap, open, b=1000mm; Keynote: d-24-000; Type Comments: max optrede 185mm, min aantrede 350mm; Type Mark: 24-08
Phasing - Phase Created: Renvooi
Calculation Rules - Maximum Riser Height: 185 mm; Minimum Run Width: 1000 mm; Minimum Tread Depth: 350 mm
Construction - Function: Interior; Landing Type: Non-Monolithic Landing: 24_STL_bordes_niet-monolitisch_hout; Run Type: Non-Monolithic Run: 24_STR_trede_staal_gegalvaniseerd_rooster_15_neus_50
Graphics - Cut Mark Type: Stair Cut Mark: 24_STCM_enkele snede
Supports - Left Lateral Offset: 0 mm; Left Support: Stringer (Closed); Left Support Type: Stringer: 24_STS_trapboom_hout_vuren_15x50; Middle Support: no; Middle Support Number: 0; Right Lateral Offset: 0 mm; Right Support: Stringer (Closed); Right Support Type: Stringer: 24_STS_trapboom_hout_vuren_15x50

# IfcStair: Assembled Stair:24_ST_stalen trap_open_b=850_op=185_aan=150:49190, Assembled Stair:Stair:69283
In: 00_begane grond
Pset_StairCommon - Reference: 24_ST_stalen trap_open_b=850_op=185_aan=150; IsExternal: no; NumberOfRiser: 17; NumberOfTreads: 16; RiserHeight: 53788.2 mm; TreadLength: 220 mm; HandicapAccessible: no; FireExit: no; HasNonSkidSurface: no
Constraints - Base Level: Level: 00_begane grond; Base Offset: 0 mm; Desired Stair Height: 3000 mm; Top Level: Level: 01_eerste verdieping; Top Offset: 0 mm
Dimensions - Actual Number of Risers: 17; Actual Riser Height: 176.471 mm; Actual Tread Depth: 220 mm; Desired Number of Risers: 17; Tread/Riser Start Number: 1
Fire Protection - brandwerend: no; ontvlambaar: no
Identity Data - antislip: no; toegankelijk: no; vluchtweg: no; Assembly Code: 2G(24.10); Description: stalen trap, open, b=1000mm; Keynote: d-24-000; Type Comments: max optrede 185mm, min aantrede 150mm; Type Mark: 24-06
Phasing - Phase Created: Renvooi
Calculation Rules - Maximum Riser Height: 185 mm; Minimum Run Width: 850 mm; Minimum Tread Depth: 150 mm
Construction - Function: Interior; Landing Type: Non-Monolithic Landing: 24_STL_bordes_niet-monolitisch_hout; Run Type: Non-Monolithic Run: 24_STR_trede_staal_gegalvaniseerd_rooster_15_neus_50
Graphics - Cut Mark Type: Stair Cut Mark: 24_STCM_enkele snede
Supports - Left Lateral Offset: 0 mm; Left Support: Stringer (Closed); Left Support Type: Stringer: 24_STS_trapboom_hout_vuren_15x50; Middle Support: no; Middle Support Number: 0; Right Lateral Offset: 0 mm; Right Support: Stringer (Closed); Right Support Type: Stringer: 24_STS_trapboom_hout_vuren_15x50

# IfcStair: Assembled Stair:24_ST_stalen trap_open_b=850_op=185_aan=220:49176, Assembled Stair:Stair:69288
In: 00_begane grond
Pset_StairCommon - Reference: 24_ST_stalen trap_open_b=850_op=185_aan=220; IsExternal: no; NumberOfRiser: 17; NumberOfTreads: 16; RiserHeight: 53788.2 mm; TreadLength: 220 mm; HandicapAccessible: no; FireExit: no; HasNonSkidSurface: no
Constraints - Base Level: Level: 00_begane grond; Base Offset: 0 mm; Desired Stair Height: 3000 mm; Top Level: Level: 01_eerste verdieping; Top Offset: 0 mm
Dimensions - Actual Number of Risers: 17; Actual Riser Height: 176.471 mm; Actual Tread Depth: 220 mm; Desired Number of Risers: 17; Tread/Riser Start Number: 1
Fire Protection - brandwerend: no; ontvlambaar: no
Identity Data - antislip: no; toegankelijk: no; vluchtweg: no; Assembly Code: 2G(24.10); Description: stalen trap, open, b=850mm; Keynote: d-24-000; Type Comments: max optrede 185mm, min aantrede 220mm; Type Mark: 24-07
Phasing - Phase Created: Renvooi
Calculation Rules - Maximum Riser Height: 185 mm; Minimum Run Width: 1000 mm; Minimum Tread Depth: 220 mm
Construction - Function: Interior; Landing Type: Non-Monolithic Landing: 24_STL_bordes_niet-monolitisch_hout; Run Type: Non-Monolithic Run: 24_STR_trede_staal_gegalvaniseerd_rooster_15_neus_50
Graphics - Cut Mark Type: Stair Cut Mark: 24_STCM_enkele snede
Supports - Left Lateral Offset: 0 mm; Left Support: Stringer (Closed); Left Support Type: Stringer: 24_STS_trapboom_hout_vuren_15x50; Middle Support: no; Middle Support Number: 0; Right Lateral Offset: 0 mm; Right Support: Stringer (Closed); Right Support Type: Stringer: 24_STS_trapboom_hout_vuren_15x50

# IfcStair: Assembled Stair:24_ST_stalen trap_open_middenboom_b=1000_op=185_aan=220:49179, Assembled Stair:Stair:69309
In: 00_begane grond
Pset_StairCommon - Reference: 24_ST_stalen trap_open_middenboom_b=1000_op=185_aan=220; IsExternal: no; NumberOfRiser: 17; NumberOfTreads: 16; RiserHeight: 53788.2 mm; TreadLength: 220 mm; HandicapAccessible: no; FireExit: no; HasNonSkidSurface: no
Constraints - Base Level: Level: 00_begane grond; Base Offset: 0 mm; Desired Stair Height: 3000 mm; Top Level: Level: 01_eerste verdieping; Top Offset: 0 mm
Dimensions - Actual Number of Risers: 17; Actual Riser Height: 176.471 mm; Actual Tread Depth: 220 mm; Desired Number of Risers: 17; Tread/Riser Start Number: 1
Fire Protection - brandwerend: no; ontvlambaar: no
Identity Data - antislip: no; toegankelijk: no; vluchtweg: no; Assembly Code: 2G(24.10); Description: stalen trap, open, met middenboom, b=1000mm; Keynote: d-24-000; Type Comments: max optrede 185mm, min aantrede 220mm; Type Mark: 24-09
Phasing - Phase Created: Renvooi
Calculation Rules - Maximum Riser Height: 185 mm; Minimum Run Width: 1000 mm; Minimum Tread Depth: 220 mm
Construction - Function: Interior; Landing Type: Non-Monolithic Landing: 24_STL_bordes_niet-monolitisch_hout; Run Type: Non-Monolithic Run: 24_STR_trede_staal_gegalvaniseerd_rooster_15_neus_50
Graphics - Cut Mark Type: Stair Cut Mark: 24_STCM_enkele snede
Supports - Left Lateral Offset: 0 mm; Middle Support: yes; Middle Support Number: 1; Middle Support Type: Carriage: 24_STC_middenboom_hout_vuren_100x50; Right Lateral Offset: 0 mm

# IfcStair: Cast-In-Place Stair:24_ST_trap_beton_ihwg_850_220_185:49169, Cast-In-Place Stair:Stair:69314
In: 00_begane grond
Pset_StairCommon - Reference: 24_ST_trap_beton_ihwg_850_220_185; IsExternal: no; NumberOfRiser: 17; NumberOfTreads: 16; RiserHeight: 53788.2 mm; TreadLength: 220 mm; HandicapAccessible: no; FireExit: no; HasNonSkidSurface: no
Constraints - Base Level: Level: 00_begane grond; Base Offset: 0 mm; Desired Stair Height: 3000 mm; Top Level: Level: 01_eerste verdieping; Top Offset: 0 mm
Dimensions - Actual Number of Risers: 17; Actual Riser Height: 176.471 mm; Actual Tread Depth: 220 mm; Desired Number of Risers: 17; Tread/Riser Start Number: 1
Fire Protection - brandwerend: no; ontvlambaar: no
Identity Data - antislip: no; toegankelijk: no; vluchtweg: no; Assembly Code: 2G(24.10); Description: betonnen trap prefab; Keynote: d-24-000; Type Comments: max optrede 185mm, min aantrede 220mm; Type Mark: 24-10
Phasing - Phase Created: Renvooi
Structural - Rebar Cover: Rebar Cover Settings: Rebar Cover 1
Calculation Rules - Maximum Riser Height: 185 mm; Minimum Run Width: 850 mm; Minimum Tread Depth: 220 mm
Construction - Function: Interior; Landing Type: Monolithic Landing: 24_STL_bordes_beton_prefab_monolitisch_300; Run Type: Monolithic Run: 24_STR_trap_beton_prefab_50_50_50
Graphics - Cut Mark Type: Stair Cut Mark: 24_STCM_enkele snede
Supports - Left Lateral Offset: 0 mm; Middle Support: no; Middle Support Number: 0; Right Lateral Offset: 0 mm

# IfcStair: Cast-In-Place Stair:24_ST_trap_beton_ihwg_monolitisch_850_220_185:2179, Cast-In-Place Stair:Stair:69318
In: 00_begane grond
Pset_StairCommon - Reference: 24_ST_trap_beton_ihwg_monolitisch_850_220_185; IsExternal: no; NumberOfRiser: 17; NumberOfTreads: 16; RiserHeight: 53788.2 mm; TreadLength: 220 mm; HandicapAccessible: no; FireExit: no; HasNonSkidSurface: no
Constraints - Base Level: Level: 00_begane grond; Base Offset: 0 mm; Desired Stair Height: 3000 mm; Top Level: Level: 01_eerste verdieping; Top Offset: 0 mm
Dimensions - Actual Number of Risers: 17; Actual Riser Height: 176.471 mm; Actual Tread Depth: 220 mm; Desired Number of Risers: 17; Tread/Riser Start Number: 1
Fire Protection - brandwerend: no; ontvlambaar: no
Identity Data - antislip: no; toegankelijk: no; vluchtweg: no; Assembly Code: 2G(24.10); Description: betonnen trap prefab monolitisch; Keynote: d-24-000; Type Comments: max optrede 185mm, min aantrede 220mm; Type Mark: 24-11
Phasing - Phase Created: Renvooi
Structural - Rebar Cover: Rebar Cover Settings: Rebar Cover 1
Calculation Rules - Maximum Riser Height: 185 mm; Minimum Run Width: 850 mm; Minimum Tread Depth: 220 mm
Construction - Function: Interior; Landing Type: Monolithic Landing: 24_STL_bordes_beton_prefab_300; Run Type: Monolithic Run: 24_STR_trap_beton_prefab_monolithisch_recht
Graphics - Cut Mark Type: Stair Cut Mark: 24_STCM_enkele snede
Supports - Left Lateral Offset: 0 mm; Middle Support: no; Middle Support Number: 0; Right Lateral Offset: 0 mm

# IfcStair: Precast Stair:24_ST_trap_beton_prefab_850_220_185:2180, Precast Stair:Stair:69323
In: 00_begane grond
Pset_StairCommon - Reference: 24_ST_trap_beton_prefab_850_220_185; IsExternal: no; NumberOfRiser: 17; NumberOfTreads: 16; RiserHeight: 53788.2 mm; TreadLength: 220 mm; HandicapAccessible: no; FireExit: no; HasNonSkidSurface: no
Constraints - Base Level: Level: 00_begane grond; Base Offset: 0 mm; Desired Stair Height: 3000 mm; Top Level: Level: 01_eerste verdieping; Top Offset: 0 mm
Dimensions - Actual Number of Risers: 17; Actual Riser Height: 176.471 mm; Actual Tread Depth: 220 mm; Desired Number of Risers: 17; Tread/Riser Start Number: 1
Fire Protection - brandwerend: no; ontvlambaar: no
Identity Data - antislip: no; toegankelijk: no; vluchtweg: no; Assembly Code: 2G(24.10); Description: betonnen trap prefab; Keynote: d-24-000; Type Comments: max optrede 185mm, min aantrede 220mm; Type Mark: 24-12
Phasing - Phase Created: Renvooi
Structural - Rebar Cover: Rebar Cover Settings: Rebar Cover 1
Calculation Rules - Maximum Riser Height: 180 mm; Minimum Run Width: 850 mm; Minimum Tread Depth: 280 mm
Construction - Function: Interior; Landing Type: Monolithic Landing: 24_STL_bordes_beton_prefab_300; Run Type: Monolithic Run: 24_STR_trap_beton_prefab_monolithisch_recht
End Connection - Connection Method: Notch; Horizontal Gap Distance: 10 mm; Notch Extension: 100 mm; Notch Thickness: 100 mm; Vertical Gap Distance: 10 mm
Supports - Left Lateral Offset: 0 mm; Middle Support: no; Middle Support Number: 0; Right Lateral Offset: 0 mm

# IfcStair: Precast Stair:24_ST_trap_beton_prefab_monolitisch_850_220_185:49192, Precast Stair:Stair:69326
In: 00_begane grond
Pset_StairCommon - Reference: 24_ST_trap_beton_prefab_monolitisch_850_220_185; IsExternal: no; NumberOfRiser: 17; NumberOfTreads: 16; RiserHeight: 53788.2 mm; TreadLength: 220 mm; HandicapAccessible: no; FireExit: no; HasNonSkidSurface: no
Constraints - Base Level: Level: 00_begane grond; Base Offset: 0 mm; Desired Stair Height: 3000 mm; Top Level: Level: 01_eerste verdieping; Top Offset: 0 mm
Dimensions - Actual Number of Risers: 17; Actual Riser Height: 176.471 mm; Actual Tread Depth: 220 mm; Desired Number of Risers: 17; Tread/Riser Start Number: 1
Fire Protection - brandwerend: no; ontvlambaar: no
Identity Data - antislip: no; toegankelijk: no; vluchtweg: no; Assembly Code: 2G(24.10); Description: betonnen trap prefab monolitisch; Keynote: d-24-000; Type Comments: max optrede 185mm, min aantrede 220mm; Type Mark: 24-13
Phasing - Phase Created: Renvooi
Structural - Rebar Cover: Rebar Cover Settings: Rebar Cover 1
Calculation Rules - Maximum Riser Height: 185 mm; Minimum Run Width: 850 mm; Minimum Tread Depth: 220 mm
Construction - Function: Interior; Landing Type: Monolithic Landing: 24_STL_bordes_beton_prefab_monolitisch_300; Run Type: Monolithic Run: 24_STR_trap_beton_prefab_50_50_50
End Connection - Connection Method: Notch; Horizontal Gap Distance: 10 mm; Notch Extension: 100 mm; Notch Thickness: 100 mm; Vertical Gap Distance: 10 mm
Graphics - Cut Mark Type: Stair Cut Mark: 24_STCM_enkele snede
Supports - Left Lateral Offset: 0 mm; Middle Support: no; Middle Support Number: 0; Right Lateral Offset: 0 mm

# IfcStairFlight: Assembled Stair:24_ST_houten trap_gesloten_b=850_op=185_aan=220:49186, Assembled Stair:Stair:68679 Run 1
In: 00_begane grond
NumberOfRiser: 17; NumberOfTreads: 16; RiserHeight: 0.578972 mm; TreadLength: 0.721785 mm
Pset_StairFlightCommon - Reference: 24_STR_trede_hout_vuren_40_neus_50_stootbord_10; NumberOfRiser: 17; NumberOfTreads: 16; RiserHeight: 176.471 mm; TreadLength: 220 mm; TreadLengthAtOffset: 220 mm; NosingLength: 15240 mm; WalkingLineOffset: 425 mm; WaistThickness: 850 mm
Constraints - Location Line: Run: Center; Relative Base Height: 0 mm; Relative Top Height: 3000 mm; Run Height: 3000 mm
Construction - Begin with Riser: yes; End with Riser: yes; Extend Below Riser Base: 0 mm
Dimensions - Actual Number of Risers: 17; Actual Number of Treads: 16; Actual Riser Height: 176.471 mm; Actual Run Width: 850 mm; Actual Tread Depth: 220 mm
Phasing - Phase Created: Renvooi
Fire Protection - ontvlambaar: no
Identity Data - Assembly Code: 2G(24.10); Description: trap hout, dicht; Keynote: d-24-000; Type Comments: trede 40mm, neus 50mm, stootbord 10mm
Risers - Riser: yes; Riser Thickness: 10 mm; Riser To Tread Connection: Extend Tread Under Riser; Slanted: no
Treads - Apply Nosing Profile: Front Only; Nosing Length: 50 mm; Tread: yes; Tread Thickness: 40 mm

# IfcStairFlight: Assembled Stair:24_ST_houten trap_open_b=850_op=185_aan=220:49184, Assembled Stair:Stair:68953 Run 1
In: 00_begane grond
NumberOfRiser: 17; NumberOfTreads: 16; RiserHeight: 0.578972 mm; TreadLength: 0.721785 mm
Pset_StairFlightCommon - Reference: 24_STR_trede_hout_vuren_40_neus_50; NumberOfRiser: 17; NumberOfTreads: 16; RiserHeight: 176.471 mm; TreadLength: 220 mm; TreadLengthAtOffset: 220 mm; NosingLength: 15240 mm; WalkingLineOffset: 425 mm; WaistThickness: 850 mm
Constraints - Location Line: Run: Center; Relative Base Height: 0 mm; Relative Top Height: 3000 mm; Run Height: 3000 mm
Construction - Begin with Riser: yes; End with Riser: yes; Extend Below Riser Base: 0 mm
Dimensions - Actual Number of Risers: 17; Actual Number of Treads: 16; Actual Riser Height: 176.471 mm; Actual Run Width: 850 mm; Actual Tread Depth: 220 mm
Phasing - Phase Created: Renvooi
Fire Protection - ontvlambaar: no
Identity Data - Assembly Code: 2G(24.10); Description: trap hout, open; Keynote: d-24-000; Type Comments: trede 40mm, neus 50mm
Risers - Riser: no; Riser Thickness: 0 mm; Riser To Tread Connection: Extend Tread Under Riser; Slanted: no
Treads - Apply Nosing Profile: Front Only; Nosing Length: 50 mm; Tread: yes; Tread Thickness: 40 mm

# IfcStairFlight: Assembled Stair:24_ST_houten trap_open_gezadeld_b=850_op=185_aan=220:49189, Assembled Stair:Stair:69257 Run 1
In: 00_begane grond
NumberOfRiser: 17; NumberOfTreads: 16; RiserHeight: 0.578972 mm; TreadLength: 0.721785 mm
Pset_StairFlightCommon - Reference: 24_STR_trede_hout_vuren_40_neus_50; NumberOfRiser: 17; NumberOfTreads: 16; RiserHeight: 176.471 mm; TreadLength: 220 mm; TreadLengthAtOffset: 220 mm; NosingLength: 15240 mm; WalkingLineOffset: 425 mm; WaistThickness: 850 mm
Constraints - Location Line: Run: Center; Relative Base Height: 0 mm; Relative Top Height: 3000 mm; Run Height: 3000 mm
Construction - Begin with Riser: yes; End with Riser: yes; Extend Below Riser Base: 0 mm
Dimensions - Actual Number of Risers: 17; Actual Number of Treads: 16; Actual Riser Height: 176.471 mm; Actual Run Width: 850 mm; Actual Tread Depth: 220 mm
Phasing - Phase Created: Renvooi
Fire Protection - ontvlambaar: no
Identity Data - Assembly Code: 2G(24.10); Description: trap hout, open; Keynote: d-24-000; Type Comments: trede 40mm, neus 50mm
Risers - Riser: no; Riser Thickness: 0 mm; Riser To Tread Connection: Extend Tread Under Riser; Slanted: no
Treads - Apply Nosing Profile: Front Only; Nosing Length: 50 mm; Tread: yes; Tread Thickness: 40 mm

# IfcStairFlight: Assembled Stair:24_ST_houten trap_open_middenboom_b=850_op=185_aan=220:49181, Assembled Stair:Stair:69261 Run 1
In: 00_begane grond
NumberOfRiser: 17; NumberOfTreads: 16; RiserHeight: 0.578972 mm; TreadLength: 0.721785 mm
Pset_StairFlightCommon - Reference: 24_STR_trede_hout_vuren_40_neus_50; NumberOfRiser: 17; NumberOfTreads: 16; RiserHeight: 176.471 mm; TreadLength: 220 mm; TreadLengthAtOffset: 220 mm; NosingLength: 15240 mm; WalkingLineOffset: 425 mm; WaistThickness: 850 mm
Constraints - Location Line: Run: Center; Relative Base Height: 0 mm; Relative Top Height: 3000 mm; Run Height: 3000 mm
Construction - Begin with Riser: yes; End with Riser: yes; Extend Below Riser Base: 0 mm
Dimensions - Actual Number of Risers: 17; Actual Number of Treads: 16; Actual Riser Height: 176.471 mm; Actual Run Width: 850 mm; Actual Tread Depth: 220 mm
Phasing - Phase Created: Renvooi
Fire Protection - ontvlambaar: no
Identity Data - Assembly Code: 2G(24.10); Description: trap hout, open; Keynote: d-24-000; Type Comments: trede 40mm, neus 50mm
Risers - Riser: no; Riser Thickness: 0 mm; Riser To Tread Connection: Extend Tread Under Riser; Slanted: no
Treads - Apply Nosing Profile: Front Only; Nosing Length: 50 mm; Tread: yes; Tread Thickness: 40 mm

# IfcStairFlight: Assembled Stair:24_ST_stalen trap_gesloten_b=1000_op=185_aan=220:49174, Assembled Stair:Stair:69280 Run 1
In: 00_begane grond
NumberOfRiser: 17; NumberOfTreads: 16; RiserHeight: 0.578972 mm; TreadLength: 0.721785 mm; Material: 24_staal_gegalvaniseerd_rooster_generiek
Pset_StairFlightCommon - Reference: 24_STR_trede_staal_gegalvaniseerd_rooster_15_neus_50_stootbord_15; NumberOfRiser: 17; NumberOfTreads: 16; RiserHeight: 176.471 mm; TreadLength: 220 mm; TreadLengthAtOffset: 220 mm; NosingLength: 15240 mm; WalkingLineOffset: 500 mm; WaistThickness: 1000 mm
Constraints - Location Line: Run: Center; Relative Base Height: 0 mm; Relative Top Height: 3000 mm; Run Height: 3000 mm
Construction - Begin with Riser: yes; End with Riser: yes; Extend Below Riser Base: 0 mm
Dimensions - Actual Number of Risers: 17; Actual Number of Treads: 16; Actual Riser Height: 176.471 mm; Actual Run Width: 1000 mm; Actual Tread Depth: 220 mm
Phasing - Phase Created: Renvooi
Fire Protection - ontvlambaar: no
Identity Data - Assembly Code: 2G(24.10); Description: trap staal gegalvaniseerd rooster, dicht; Keynote: d-24-000; Type Comments: trede 15mm, neus 50mm, stootbord 15mm
Materials and Finishes - Riser Material: 24_staal_gegalvaniseerd_rooster_generiek; Tread Material: 24_staal_gegalvaniseerd_rooster_generiek
Risers - Riser: yes; Riser Thickness: 15 mm; Riser To Tread Connection: Extend Tread Under Riser; Slanted: no
Treads - Apply Nosing Profile: Front Only; Nosing Length: 50 mm; Tread: yes; Tread Thickness: 15 mm

# IfcStairFlight: Assembled Stair:24_ST_stalen trap_open_b=1000_op=185_aan=350:49191, Assembled Stair:Stair:69305 Run 1
In: 00_begane grond
NumberOfRiser: 17; NumberOfTreads: 16; RiserHeight: 0.578972 mm; TreadLength: 0.721785 mm; Material: 24_staal_gegalvaniseerd_rooster_generiek
Pset_StairFlightCommon - Reference: 24_STR_trede_staal_gegalvaniseerd_rooster_15_neus_50; NumberOfRiser: 17; NumberOfTreads: 16; RiserHeight: 176.471 mm; TreadLength: 220 mm; TreadLengthAtOffset: 220 mm; NosingLength: 15240 mm; WalkingLineOffset: 500 mm; WaistThickness: 1000 mm
Constraints - Location Line: Run: Center; Relative Base Height: 0 mm; Relative Top Height: 3000 mm; Run Height: 3000 mm
Construction - Begin with Riser: yes; End with Riser: yes; Extend Below Riser Base: 0 mm
Dimensions - Actual Number of Risers: 17; Actual Number of Treads: 16; Actual Riser Height: 176.471 mm; Actual Run Width: 1000 mm; Actual Tread Depth: 220 mm
Phasing - Phase Created: Renvooi
Fire Protection - ontvlambaar: no
Identity Data - Assembly Code: 2G(24.10); Description: trap staal gegalvaniseerd rooster, open; Keynote: d-24-000; Type Comments: trede 15mm, neus 50mm
Materials and Finishes - Tread Material: 24_staal_gegalvaniseerd_rooster_generiek
Risers - Riser: no; Riser Thickness: 0 mm; Riser To Tread Connection: Extend Tread Under Riser; Slanted: no
Treads - Apply Nosing Profile: Front Only; Nosing Length: 50 mm; Tread: yes; Tread Thickness: 15 mm

# IfcStairFlight: Assembled Stair:24_ST_stalen trap_open_b=850_op=185_aan=150:49190, Assembled Stair:Stair:69283 Run 1
In: 00_begane grond
NumberOfRiser: 17; NumberOfTreads: 16; RiserHeight: 0.578972 mm; TreadLength: 0.721785 mm; Material: 24_staal_gegalvaniseerd_rooster_generiek
Pset_StairFlightCommon - Reference: 24_STR_trede_staal_gegalvaniseerd_rooster_15_neus_50; NumberOfRiser: 17; NumberOfTreads: 16; RiserHeight: 176.471 mm; TreadLength: 220 mm; TreadLengthAtOffset: 220 mm; NosingLength: 15240 mm; WalkingLineOffset: 425 mm; WaistThickness: 850 mm
Constraints - Location Line: Run: Center; Relative Base Height: 0 mm; Relative Top Height: 3000 mm; Run Height: 3000 mm
Construction - Begin with Riser: yes; End with Riser: yes; Extend Below Riser Base: 0 mm
Dimensions - Actual Number of Risers: 17; Actual Number of Treads: 16; Actual Riser Height: 176.471 mm; Actual Run Width: 850 mm; Actual Tread Depth: 220 mm
Phasing - Phase Created: Renvooi
Fire Protection - ontvlambaar: no
Identity Data - Assembly Code: 2G(24.10); Description: trap staal gegalvaniseerd rooster, open; Keynote: d-24-000; Type Comments: trede 15mm, neus 50mm
Materials and Finishes - Tread Material: 24_staal_gegalvaniseerd_rooster_generiek
Risers - Riser: no; Riser Thickness: 0 mm; Riser To Tread Connection: Extend Tread Under Riser; Slanted: no
Treads - Apply Nosing Profile: Front Only; Nosing Length: 50 mm; Tread: yes; Tread Thickness: 15 mm

# IfcStairFlight: Assembled Stair:24_ST_stalen trap_open_b=850_op=185_aan=220:49176, Assembled Stair:Stair:69288 Run 1
In: 00_begane grond
NumberOfRiser: 17; NumberOfTreads: 16; RiserHeight: 0.578972 mm; TreadLength: 0.721785 mm; Material: 24_staal_gegalvaniseerd_rooster_generiek
Pset_StairFlightCommon - Reference: 24_STR_trede_staal_gegalvaniseerd_rooster_15_neus_50; NumberOfRiser: 17; NumberOfTreads: 16; RiserHeight: 176.471 mm; TreadLength: 220 mm; TreadLengthAtOffset: 220 mm; NosingLength: 15240 mm; WalkingLineOffset: 425 mm; WaistThickness: 850 mm
Constraints - Location Line: Run: Center; Relative Base Height: 0 mm; Relative Top Height: 3000 mm; Run Height: 3000 mm
Construction - Begin with Riser: yes; End with Riser: yes; Extend Below Riser Base: 0 mm
Dimensions - Actual Number of Risers: 17; Actual Number of Treads: 16; Actual Riser Height: 176.471 mm; Actual Run Width: 850 mm; Actual Tread Depth: 220 mm
Phasing - Phase Created: Renvooi
Fire Protection - ontvlambaar: no
Identity Data - Assembly Code: 2G(24.10); Description: trap staal gegalvaniseerd rooster, open; Keynote: d-24-000; Type Comments: trede 15mm, neus 50mm
Materials and Finishes - Tread Material: 24_staal_gegalvaniseerd_rooster_generiek
Risers - Riser: no; Riser Thickness: 0 mm; Riser To Tread Connection: Extend Tread Under Riser; Slanted: no
Treads - Apply Nosing Profile: Front Only; Nosing Length: 50 mm; Tread: yes; Tread Thickness: 15 mm

# IfcStairFlight: Assembled Stair:24_ST_stalen trap_open_middenboom_b=1000_op=185_aan=220:49179, Assembled Stair:Stair:69309 Run 1
In: 00_begane grond
NumberOfRiser: 17; NumberOfTreads: 16; RiserHeight: 0.578972 mm; TreadLength: 0.721785 mm; Material: 24_staal_gegalvaniseerd_rooster_generiek
Pset_StairFlightCommon - Reference: 24_STR_trede_staal_gegalvaniseerd_rooster_15_neus_50; NumberOfRiser: 17; NumberOfTreads: 16; RiserHeight: 176.471 mm; TreadLength: 220 mm; TreadLengthAtOffset: 220 mm; NosingLength: 15240 mm; WalkingLineOffset: 500 mm; WaistThickness: 1000 mm
Constraints - Location Line: Run: Center; Relative Base Height: 0 mm; Relative Top Height: 3000 mm; Run Height: 3000 mm
Construction - Begin with Riser: yes; End with Riser: yes; Extend Below Riser Base: 0 mm
Dimensions - Actual Number of Risers: 17; Actual Number of Treads: 16; Actual Riser Height: 176.471 mm; Actual Run Width: 1000 mm; Actual Tread Depth: 220 mm
Phasing - Phase Created: Renvooi
Fire Protection - ontvlambaar: no
Identity Data - Assembly Code: 2G(24.10); Description: trap staal gegalvaniseerd rooster, open; Keynote: d-24-000; Type Comments: trede 15mm, neus 50mm
Materials and Finishes - Tread Material: 24_staal_gegalvaniseerd_rooster_generiek
Risers - Riser: no; Riser Thickness: 0 mm; Riser To Tread Connection: Extend Tread Under Riser; Slanted: no
Treads - Apply Nosing Profile: Front Only; Nosing Length: 50 mm; Tread: yes; Tread Thickness: 15 mm

# IfcStairFlight: Cast-In-Place Stair:24_ST_trap_beton_ihwg_850_220_185:49169, Cast-In-Place Stair:Stair:69314 Run 1
In: 00_begane grond
NumberOfRiser: 17; NumberOfTreads: 16; RiserHeight: 0.578972 mm; TreadLength: 0.721785 mm; Material: 24_beton_prefab_generiek
Pset_StairFlightCommon - Reference: 24_STR_trap_beton_prefab_50_50_50; NumberOfRiser: 17; NumberOfTreads: 16; RiserHeight: 176.471 mm; TreadLength: 220 mm; TreadLengthAtOffset: 220 mm; NosingLength: 15240 mm; WalkingLineOffset: 425 mm; WaistThickness: 850 mm
Constraints - Location Line: Run: Center; Relative Base Height: 0 mm; Relative Top Height: 3000 mm; Run Height: 3000 mm
Construction - Begin with Riser: yes; End with Riser: yes; Extend Below Riser Base: 0 mm; Structural Depth: 150 mm; Underside Surface: Smooth
Dimensions - Actual Number of Risers: 17; Actual Number of Treads: 16; Actual Riser Height: 176.471 mm; Actual Run Width: 850 mm; Actual Tread Depth: 220 mm
Phasing - Phase Created: Renvooi
Fire Protection - ontvlambaar: no
Identity Data - Assembly Code: 2G(24.10); Description: trap beton, monolitisch, prefab, recht; Keynote: d-24-000; Type Comments: trede 50mm, neus 50mm, stootbord 50mm
Materials and Finishes - Monolithic Material: 24_beton_prefab_generiek; Riser Material: 24_beton_prefab_generiek; Tread Material: 24_beton_prefab_generiek
Risers - Riser: yes; Riser Thickness: 50 mm; Riser To Tread Connection: Join All Risers And Treads; Slanted: no
Treads - Apply Nosing Profile: Front Only; Nosing Length: 50 mm; Tread: yes; Tread Thickness: 50 mm

# IfcStairFlight: Cast-In-Place Stair:24_ST_trap_beton_ihwg_monolitisch_850_220_185:2179, Cast-In-Place Stair:Stair:69318 Run 1
In: 00_begane grond
NumberOfRiser: 17; NumberOfTreads: 16; RiserHeight: 0.578972 mm; TreadLength: 0.721785 mm; Material: 24_beton_prefab_generiek
Pset_StairFlightCommon - Reference: 24_STR_trap_beton_prefab_monolithisch_recht; NumberOfRiser: 17; NumberOfTreads: 16; RiserHeight: 176.471 mm; TreadLength: 220 mm; TreadLengthAtOffset: 220 mm; NosingLength: 0 mm; WalkingLineOffset: 425 mm; WaistThickness: 850 mm
Constraints - Location Line: Run: Center; Relative Base Height: 0 mm; Relative Top Height: 3000 mm; Run Height: 3000 mm
Construction - Begin with Riser: yes; End with Riser: yes; Extend Below Riser Base: 0 mm; Structural Depth: 150 mm; Underside Surface: Smooth
Dimensions - Actual Number of Risers: 17; Actual Number of Treads: 16; Actual Riser Height: 176.471 mm; Actual Run Width: 850 mm; Actual Tread Depth: 220 mm
Phasing - Phase Created: Renvooi
Fire Protection - ontvlambaar: no
Identity Data - Assembly Code: 2G(24.10); Description: trap beton, monolitisch, prefab, recht; Keynote: d-24-000; Type Comments: constructieve dikte = 150mm
Materials and Finishes - Monolithic Material: 24_beton_prefab_generiek
Risers - Riser: no; Riser Thickness: 0 mm; Riser To Tread Connection: Extend Riser Behind Tread; Slanted: no
Treads - Apply Nosing Profile: Front Only; Nosing Length: 0 mm; Tread: no; Tread Thickness: 0 mm

# IfcStairFlight: Precast Stair:24_ST_trap_beton_prefab_850_220_185:2180, Precast Stair:Stair:69323 Run 1
In: 00_begane grond
NumberOfRiser: 17; NumberOfTreads: 16; RiserHeight: 0.578972 mm; TreadLength: 0.721785 mm; Material: 24_beton_prefab_generiek
Pset_StairFlightCommon - Reference: 24_STR_trap_beton_prefab_monolithisch_recht; NumberOfRiser: 17; NumberOfTreads: 16; RiserHeight: 176.471 mm; TreadLength: 220 mm; TreadLengthAtOffset: 220 mm; NosingLength: 0 mm; WalkingLineOffset: 425 mm; WaistThickness: 850 mm
Constraints - Location Line: Run: Center; Relative Base Height: 0 mm; Relative Top Height: 3000 mm; Run Height: 3000 mm
Construction - Begin with Riser: yes; End with Riser: yes; Extend Below Riser Base: 0 mm; Structural Depth: 150 mm; Underside Surface: Smooth
Dimensions - Actual Number of Risers: 17; Actual Number of Treads: 16; Actual Riser Height: 176.471 mm; Actual Run Width: 850 mm; Actual Tread Depth: 220 mm
Phasing - Phase Created: Renvooi
Fire Protection - ontvlambaar: no
Identity Data - Assembly Code: 2G(24.10); Description: trap beton, monolitisch, prefab, recht; Keynote: d-24-000; Type Comments: constructieve dikte = 150mm
Materials and Finishes - Monolithic Material: 24_beton_prefab_generiek
Risers - Riser: no; Riser Thickness: 0 mm; Riser To Tread Connection: Extend Riser Behind Tread; Slanted: no
Treads - Apply Nosing Profile: Front Only; Nosing Length: 0 mm; Tread: no; Tread Thickness: 0 mm

# IfcStairFlight: Precast Stair:24_ST_trap_beton_prefab_monolitisch_850_220_185:49192, Precast Stair:Stair:69326 Run 1
In: 00_begane grond
NumberOfRiser: 17; NumberOfTreads: 16; RiserHeight: 0.578972 mm; TreadLength: 0.721785 mm; Material: 24_beton_prefab_generiek
Pset_StairFlightCommon - Reference: 24_STR_trap_beton_prefab_50_50_50; NumberOfRiser: 17; NumberOfTreads: 16; RiserHeight: 176.471 mm; TreadLength: 220 mm; TreadLengthAtOffset: 220 mm; NosingLength: 15240 mm; WalkingLineOffset: 425 mm; WaistThickness: 850 mm
Constraints - Location Line: Run: Center; Relative Base Height: 0 mm; Relative Top Height: 3000 mm; Run Height: 3000 mm
Construction - Begin with Riser: yes; End with Riser: yes; Extend Below Riser Base: 0 mm; Structural Depth: 150 mm; Underside Surface: Smooth
Dimensions - Actual Number of Risers: 17; Actual Number of Treads: 16; Actual Riser Height: 176.471 mm; Actual Run Width: 850 mm; Actual Tread Depth: 220 mm
Phasing - Phase Created: Renvooi
Fire Protection - ontvlambaar: no
Identity Data - Assembly Code: 2G(24.10); Description: trap beton, monolitisch, prefab, recht; Keynote: d-24-000; Type Comments: trede 50mm, neus 50mm, stootbord 50mm
Materials and Finishes - Monolithic Material: 24_beton_prefab_generiek; Riser Material: 24_beton_prefab_generiek; Tread Material: 24_beton_prefab_generiek
Risers - Riser: yes; Riser Thickness: 50 mm; Riser To Tread Connection: Join All Risers And Treads; Slanted: no
Treads - Apply Nosing Profile: Front Only; Nosing Length: 50 mm; Tread: yes; Tread Thickness: 50 mm

# IfcWallStandardCase: Basic Wall:20_WA_wand_generiek_100 (7)
In: 00_begane grond
Type - PredefinedType: STANDARD; Material: Default 100 mm
Type - Analytical Properties - Absorptance: 0.1; Roughness: 1
Type - Construction - Function: Exterior; Width: 100 mm; Wrapping at Inserts: Do not wrap
Type - Fire Protection - ontvlambaar: no
Type - Graphics - Coarse Scale Fill Color: 8421504; Coarse Scale Fill Pattern: Solid fill
Type - Identity Data - Assembly Code: 2D(21.0); Description: buitenwand, generiek; Keynote: d-21-000; Type Mark: 21-01
Constraints - Base Constraint: Level: 00_begane grond; Base Extension Distance: 0 mm; Base is Attached: no; Base Offset: 0 mm; Related to Mass: no; Room Bounding: yes; Top Extension Distance: 0 mm; Top is Attached: no; Top Offset: 0 mm
Fire Protection - brandwerend: no
Phasing - Phase Created: Renvooi
Structural - Enable Analytical Model: no; Structural: no; Structural Usage: Non-bearing
Pset_WallCommon - Reference: 20_WA_wand_generiek_100; LoadBearing: no; ExtendToStructure: no; IsExternal: yes; Combustible: no; Compartmentation: no
PSet_COBIE - NominalWidth: 100
Name (Basic Wall:20_WA_wand_generiek_100:...) | Location Line | Unconnected Height (mm) | Area (m2) | Length (mm) = NominalLength | Volume (m3)
30521 | Core Face: Exterior | 2000 | 4 | 2000 | 0.4
317191 | Wall Centerline | 4000 | 6 | 1500 | 0.6
317289 | Wall Centerline | 4000 | 6 | 1500 | 0.6
317373 | Wall Centerline | 4000 | 6 | 1500 | 0.6
317419 | Wall Centerline | 4000 | 6 | 1500 | 0.6
317422 | Wall Centerline | 4000 | 6 | 1500 | 0.6
317425 | Wall Centerline | 4000 | 6 | 1500 | 0.6

# IfcWallStandardCase: Basic Wall:20_WA_wand_generiek_200, Basic Wall:20_WA_wand_generiek_200:30552
In: 00_begane grond
Type - PredefinedType: STANDARD; Material: Default 200 mm
Type - Analytical Properties - Absorptance: 0.1; Roughness: 1
Type - Construction - Function: Exterior; Width: 200 mm; Wrapping at Inserts: Do not wrap
Type - Fire Protection - ontvlambaar: no
Type - Graphics - Coarse Scale Fill Color: 8421504; Coarse Scale Fill Pattern: Solid fill
Type - Identity Data - Assembly Code: 2D(21.0); Description: buitenwand, generiek; Keynote: d-21-000; Type Mark: 21-02
Constraints - Base Constraint: Level: 00_begane grond; Base Extension Distance: 0 mm; Base is Attached: no; Base Offset: 0 mm; Location Line: Core Face: Exterior; Related to Mass: no; Room Bounding: yes; Top Extension Distance: 0 mm; Top is Attached: no; Top Offset: 0 mm; Unconnected Height: 2000 mm
Dimensions - Area: 4 m2; Length: 2000 mm; Volume: 0.8 m3
Fire Protection - brandwerend: no
Phasing - Phase Created: Renvooi
Structural - Enable Analytical Model: yes; Rebar Cover - Exterior Face: Rebar Cover Settings: Rebar Cover 1; Rebar Cover - Interior Face: Rebar Cover Settings: Rebar Cover 1; Rebar Cover - Other Faces: Rebar Cover Settings: Rebar Cover 1; Structural: yes; Structural Usage: Bearing
Pset_WallCommon - Reference: 20_WA_wand_generiek_200; LoadBearing: yes; ExtendToStructure: no; IsExternal: yes; Combustible: no; Compartmentation: no
PSet_COBIE - NominalLength: 2000; NominalWidth: 200

# IfcWallStandardCase: Basic Wall:20_WA_wand_generiek_300, Basic Wall:20_WA_wand_generiek_300:30825
In: 00_begane grond
Type - PredefinedType: STANDARD; Material: Default 300 mm
Type - Analytical Properties - Absorptance: 0.1; Roughness: 1
Type - Construction - Function: Exterior; Width: 300 mm; Wrapping at Inserts: Do not wrap
Type - Fire Protection - ontvlambaar: no
Type - Graphics - Coarse Scale Fill Color: 8421504; Coarse Scale Fill Pattern: Solid fill
Type - Identity Data - Assembly Code: 2D(21.0); Description: buitenwand, generiek; Keynote: d-21-000; Type Mark: 21-03
Constraints - Base Constraint: Level: 00_begane grond; Base Extension Distance: 0 mm; Base is Attached: no; Base Offset: 0 mm; Location Line: Core Face: Exterior; Related to Mass: no; Room Bounding: yes; Top Extension Distance: 0 mm; Top is Attached: no; Top Offset: 0 mm; Unconnected Height: 2000 mm
Dimensions - Area: 4 m2; Length: 2000 mm; Volume: 1.2 m3
Fire Protection - brandwerend: no
Phasing - Phase Created: Renvooi
Structural - Enable Analytical Model: yes; Rebar Cover - Exterior Face: Rebar Cover Settings: Rebar Cover 1; Rebar Cover - Interior Face: Rebar Cover Settings: Rebar Cover 1; Rebar Cover - Other Faces: Rebar Cover Settings: Rebar Cover 1; Structural: yes; Structural Usage: Bearing
Pset_WallCommon - Reference: 20_WA_wand_generiek_300; LoadBearing: yes; ExtendToStructure: no; IsExternal: yes; Combustible: no; Compartmentation: no
PSet_COBIE - NominalLength: 2000; NominalWidth: 300

# IfcWallStandardCase: Basic Wall:21_WA_hout-wrc-hor_rachel_tengel_iso-sw_180_20-30-10-120, Basic Wall:21_WA_hout-wrc-hor_rachel_tengel_iso-sw_180_20-30-10-120:37447
In: 00_begane grond
Type - PredefinedType: STANDARD; Material: 41_hout_hardhout_geveldelen_donkerblauw_horizontaal 20 mm, 40_regelwerk_geventileerd 30 mm, 40_regelwerk_geventileerd 10 mm, 20_isolatie_steenwol 120 mm
Type - Analytical Properties - Absorptance: 0.1; Heat Transfer Coefficient (U): 0.274174; Roughness: 1; Thermal mass: 47139.2; Thermal Resistance (R): 3.64732
Type - Construction - Function: Exterior; Width: 180 mm; Wrapping at Inserts: Exterior
Type - Fire Protection - ontvlambaar: no
Type - Graphics - Coarse Scale Fill Color: 8421504; Coarse Scale Fill Pattern: Solid fill
Type - Identity Data - Assembly Code: 2D(21.13); Description: buitenwand, horizontale houten geveldelen, 120mm isolatie steenwol; Keynote: d-21-000; Type Comments: geveldelen op regelwerk: vert 20x30mm op hor 10x30mm; Type Mark: 21-14
Type - Materials and Finishes - Structural Material: 20_isolatie_steenwol
